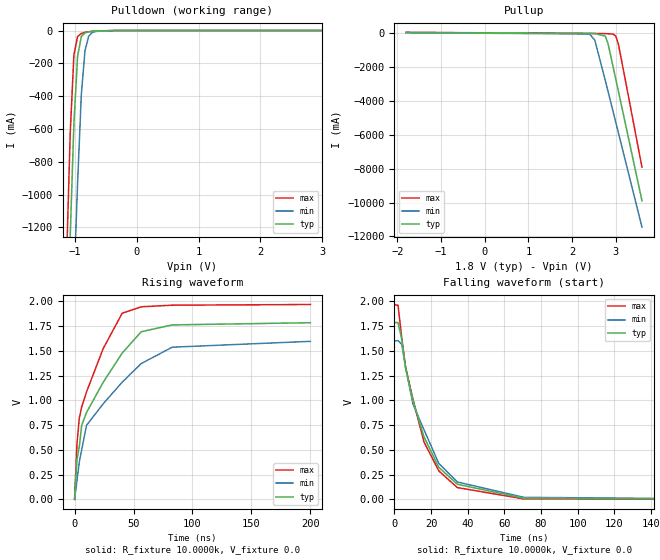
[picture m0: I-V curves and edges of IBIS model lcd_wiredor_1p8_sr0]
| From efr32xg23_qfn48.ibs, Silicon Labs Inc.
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|   Model lcd_wiredor_1p8_sr0
[Model]  lcd_wiredor_1p8_sr0
Model_type Output
Polarity   Non-Inverting
Enable   Active-Low
C_comp   1.6300pF   1.4000pF   2.7000pF
[Temperature Range]   25.0000   0.1250k   -40.0000
[Pullup Reference]   1.8000V   1.6200V   1.9800V
[Pulldown Reference]   0.0V   0.0V   0.0V
[POWER Clamp Reference]   1.8000V   1.6200V   1.9800V
[GND Clamp Reference]   0.0V   0.0V   0.0V
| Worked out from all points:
|   slope of the pullup table from 0 to 0.27 V, typ, clamps not added: 94.5 ohm
|   rising waveform, R_fixture 10.0000k, V_fixture 0.0: 20-80 % time 35.6ns typ, 44.7ns min, 24.8ns max; typ from 0 V to 1.78 V
|   falling waveform, R_fixture 10.0000k, V_fixture 0.0: 20-80 % time 17.6ns typ, 19.2ns min, 16.2ns max; typ from 1.78 V to 0 V
[Pulldown]
|Voltage   I(typ)   I(min)   I(max)
-1.8V     -9.867A    -9.569A    -10.32A
-1.14V    -1.973A    -2.773A    -1.419A
-1.08V    -1.26A     -2.157A    -630.4mA
-1.02V    -568mA     -1.543A    -149.7mA
-960mV    -155.8mA   -930mA     -35.74mA
-900mV    -37.3mA    -392mA     -18.17mA
-840mV    -13.92mA   -121.5mA   -10.46mA
-780mV    -8.725mA   -34.03mA   -7.422mA
-720mV    -4.294mA   -11.21mA   -4.92mA
-660mV    -2.711mA   -5.267mA   -2.939mA
-360mV    -18.79uA   -69.64uA   -6.715uA
3.6V      3.264nA    104.4nA    3.919nA
[Pullup]
|Voltage   I(typ)   I(min)   I(max)
-1.8V     44.26mA    33.72mA    55.37mA
2.4V      -9.562mA   -43.33mA   -10.84mA
2.52V     -13.93mA   -402.8mA   -11.94mA
2.76V     -169.7mA   -2.785A    -22.6mA
2.82V     -580.7mA   -3.402A    -26.69mA
2.94V     -1.986A    -4.637A    -50.48mA
3V        -2.702A    -5.256A    -164.4mA
3.06V     -3.418A    -5.874A    -642.8mA
3.12V     -4.136A    -6.493A    -1.431A
3.24V     -5.572A    -7.731A    -3.044A
3.3V      -6.291A    -8.35A     -3.852A
3.6V      -9.889A    -11.45A    -7.906A
[Ramp]
| variable   typ   min   max
dV/dt_r  1.0697/35.6318n   0.9571/44.7077n   1.1804/24.8364n
dV/dt_f  23.4738u/1.8662p   35.5334u/4.9249p   18.1164u/56.1366p
R_load = 10.0000k
[Rising Waveform]
R_fixture= 10.0000k
V_fixture= 0.0
V_fixture_min= 0.0
V_fixture_max= 0.0
|time   V(typ)   V(min)   V(max)
0s        3.312uV    55.57uV    2.87uV
2.02ns    400mV      185.7mV    558.5mV
4.04ns    537mV      380.3mV    823.1mV
6.061ns   747.9mV    500.8mV    933.8mV
10.1ns    875.7mV    745.9mV    1.083V
24.24ns   1.181V     964mV      1.521V
40.4ns    1.477V     1.183V     1.879V
56.57ns   1.692V     1.371V     1.944V
82.83ns   1.761V     1.536V     1.96V
200ns     1.783V     1.595V     1.967V
[Falling Waveform]
R_fixture= 10.0000k
V_fixture= 0.0
V_fixture_min= 0.0
V_fixture_max= 0.0
|time   V(typ)   V(min)   V(max)
0s        1.785V     1.6V       1.968V
2.02ns    1.786V     1.603V     1.959V
4.04ns    1.617V     1.565V     1.631V
6.061ns   1.329V     1.344V     1.343V
10.1ns    1.001V     964.5mV    1.013V
16.16ns   631.1mV    702.6mV    579.3mV
24.24ns   322.4mV    361.9mV    286.7mV
34.34ns   151.7mV    174.7mV    118.4mV
70.71ns   10.08mV    19.66mV    2.932mV
200ns     -102.5uV   787.1uV    -488.7uV
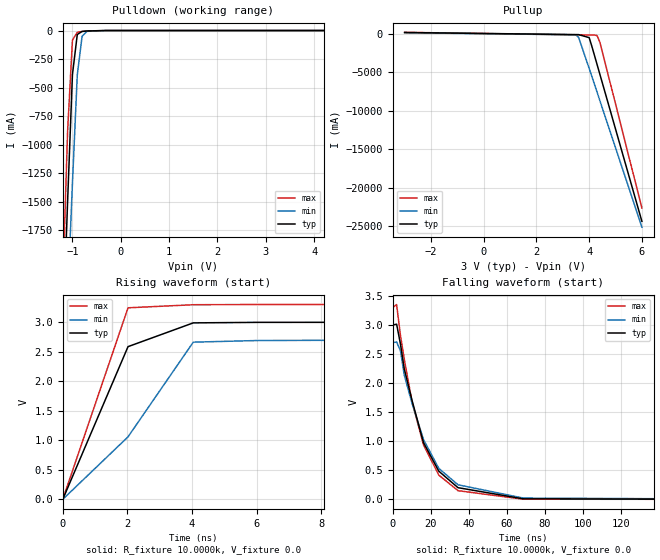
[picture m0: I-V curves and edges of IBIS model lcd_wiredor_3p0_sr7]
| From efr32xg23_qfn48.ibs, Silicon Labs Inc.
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|   Model lcd_wiredor_3p0_sr7
[Model]  lcd_wiredor_3p0_sr7
Model_type Output
Polarity   Non-Inverting
Enable   Active-Low
C_comp   1.6300pF   1.4000pF   2.7000pF
[Temperature Range]   25.0000   0.1250k   -40.0000
[Pullup Reference]   3.0000V   2.7000V   3.3000V
[Pulldown Reference]   0.0V   0.0V   0.0V
[POWER Clamp Reference]   3.0000V   2.7000V   3.3000V
[GND Clamp Reference]   0.0V   0.0V   0.0V
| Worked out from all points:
|   slope of the pullup table from 0 to 0.45 V, typ, clamps not added: 16.9 ohm
|   rising waveform, R_fixture 10.0000k, V_fixture 0.0: 20-80 % time 1.41ns typ, 2.38ns min, 1.23ns max; typ from 0 V to 3 V
|   falling waveform, R_fixture 10.0000k, V_fixture 0.0: 20-80 % time 16.5ns typ, 18.1ns min, 14.8ns max; typ from 3 V to 0 V
[Pulldown]
|Voltage   I(typ)   I(min)   I(max)
-3V       -24.27A    -21.95A    -26.57A
-1.2V     -2.686A    -3.389A    -2.22A
-1.1V     -1.495A    -2.361A    -881.8mA
-1V       -385.8mA   -1.337A    -84.19mA
-900mV    -34.99mA   -390.7mA   -14.95mA
-800mV    -7.703mA   -50.4mA    -8.403mA
-700mV    -3.742mA   -7.062mA   -4.219mA
-300mV    -2.847uA   -17.98uA   -692.6nA
6V        338.2nA    35.99uA    408.8nA
[Pullup]
|Voltage   I(typ)   I(min)   I(max)
-3V       194.2mA    164.1mA    218.3mA
3.5V      -78.04mA   -106.9mA   -111.5mA
3.6V      -80.27mA   -448.8mA   -111.7mA
4V        -471.9mA   -4.48A     -119.8mA
4.1V      -1.581A    -5.511A    -126.2mA
4.2V      -2.773A    -6.543A    -134.9mA
4.3V      -3.971A    -7.574A    -205.9mA
4.4V      -5.168A    -8.607A    -1.001A
4.5V      -6.366A    -9.639A    -2.34A
4.7V      -8.765A    -11.71A    -5.039A
4.8V      -9.964A    -12.74A    -6.39A
6V        -24.38A    -25.14A    -22.65A
[Ramp]
| variable   typ   min   max
dV/dt_r  1.7971/1.4057n   1.6163/2.3758n   1.9776/1.2331n
dV/dt_f  0.1139m/6.6269p   65.8711u/5.4048p   0.2002m/5.3470p
R_load = 10.0000k
[Rising Waveform]
R_fixture= 10.0000k
V_fixture= 0.0
V_fixture_min= 0.0
V_fixture_max= 0.0
|time   V(typ)   V(min)   V(max)
0s        4.624uV    47.91uV    4.748uV
2.02ns    2.583V     1.057V     3.24V
4.04ns    2.985V     2.659V     3.292V
6.061ns   2.994V     2.687V     3.296V
10.1ns    2.995V     2.693V     3.296V
200ns     2.995V     2.694V     3.296V
[Falling Waveform]
R_fixture= 10.0000k
V_fixture= 0.0
V_fixture_min= 0.0
V_fixture_max= 0.0
|time   V(typ)   V(min)   V(max)
0s        2.995V     2.694V     3.296V
2.02ns    3.01V      2.704V     3.348V
4.04ns    2.669V     2.555V     2.819V
6.061ns   2.239V     2.133V     2.405V
10.1ns    1.704V     1.654V     1.683V
16.16ns   975.4mV    1.028V     935.8mV
24.24ns   482.8mV    530.4mV    415.6mV
34.34ns   199.7mV    249.3mV    148.2mV
68.69ns   8.111mV    21.08mV    1.35mV
200ns     -452.2uV   289.4uV    -558.7uV
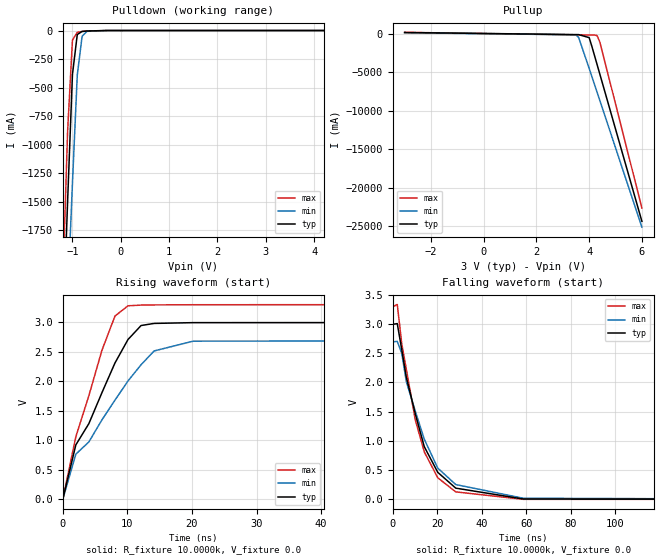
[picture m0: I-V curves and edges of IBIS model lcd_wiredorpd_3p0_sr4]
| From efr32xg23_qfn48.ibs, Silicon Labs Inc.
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|   Model lcd_wiredorpd_3p0_sr4
[Model]  lcd_wiredorpd_3p0_sr4
Model_type Output
Polarity   Non-Inverting
Enable   Active-Low
C_comp   1.6300pF   1.4000pF   2.7000pF
[Temperature Range]   25.0000   0.1250k   -40.0000
[Pullup Reference]   3.0000V   2.7000V   3.3000V
[Pulldown Reference]   0.0V   0.0V   0.0V
[POWER Clamp Reference]   3.0000V   2.7000V   3.3000V
[GND Clamp Reference]   0.0V   0.0V   0.0V
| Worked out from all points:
|   slope of the pulldown table from 0 to 0.45 V, typ, clamps not added: 40 kohm
|   slope of the pullup table from 0 to 0.45 V, typ, clamps not added: 16.9 ohm
|   rising waveform, R_fixture 10.0000k, V_fixture 0.0: 20-80 % time 7.22ns typ, 9.8ns min, 5.21ns max; typ from 0 V to 3 V
|   falling waveform, R_fixture 10.0000k, V_fixture 0.0: 20-80 % time 13.1ns typ, 14.6ns min, 11.6ns max; typ from 3 V to 0 V
[Pulldown]
|Voltage   I(typ)   I(min)   I(max)
-3V       -24.27A    -21.95A    -26.57A
-1.2V     -2.686A    -3.389A    -2.22A
-1.1V     -1.495A    -2.361A    -881.8mA
-1V       -385.8mA   -1.337A    -84.2mA
-900mV    -35.01mA   -390.8mA   -14.96mA
-800mV    -7.715mA   -50.41mA   -8.418mA
-700mV    -3.753mA   -7.071mA   -4.233mA
-300mV    -10.27uA   -24.2uA    -9.353uA
6V        150.3uA    165.9uA    174.4uA
[Pullup]
|Voltage   I(typ)   I(min)   I(max)
-3V       194.2mA    164.1mA    218.3mA
3.5V      -78.04mA   -106.9mA   -111.5mA
3.6V      -80.27mA   -448.8mA   -111.7mA
4V        -471.9mA   -4.48A     -119.8mA
4.1V      -1.581A    -5.511A    -126.2mA
4.2V      -2.773A    -6.543A    -134.9mA
4.3V      -3.971A    -7.574A    -205.9mA
4.4V      -5.168A    -8.607A    -1.001A
4.5V      -6.366A    -9.639A    -2.34A
4.7V      -8.765A    -11.71A    -5.039A
4.8V      -9.964A    -12.74A    -6.39A
6V        -24.38A    -25.14A    -22.65A
[Ramp]
| variable   typ   min   max
dV/dt_r  1.7971/7.2192n   1.6163/9.7974n   1.9776/5.2059n
dV/dt_f  0.3602/8.0619n   0.2884/10.2807n   0.4453/7.8494n
R_load = 10.0000k
[Rising Waveform]
R_fixture= 10.0000k
V_fixture= 0.0
V_fixture_min= 0.0
V_fixture_max= 0.0
|time   V(typ)   V(min)   V(max)
0s        3.563uV    38.12uV    3.534uV
2.02ns    921.1mV    764mV      1.059V
4.04ns    1.281V     970.8mV    1.754V
6.061ns   1.804V     1.344V     2.521V
8.081ns   2.307V     1.678V     3.101V
10.1ns    2.704V     2.003V     3.274V
12.12ns   2.94V      2.277V     3.286V
14.14ns   2.976V     2.51V      3.289V
20.2ns    2.989V     2.676V     3.292V
200ns     2.995V     2.694V     3.296V
[Falling Waveform]
R_fixture= 10.0000k
V_fixture= 0.0
V_fixture_min= 0.0
V_fixture_max= 0.0
|time   V(typ)   V(min)   V(max)
0s        2.995V     2.694V     3.296V
2.02ns    3.007V     2.703V     3.334V
4.04ns    2.559V     2.497V     2.661V
6.061ns   2.093V     2.016V     2.231V
10.1ns    1.465V     1.509V     1.36V
14.14ns   900.8mV    1.029V     812.1mV
20.2ns    461.4mV    533.7mV    368.2mV
28.28ns   190.7mV    252.1mV    126.5mV
58.59ns   5.202mV    17.91mV    -671.9uV
200ns     -336.2uV   209.1uV    -398uV
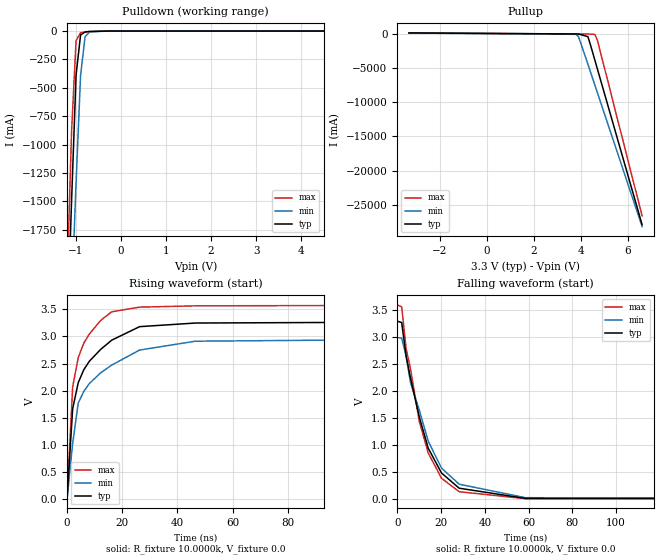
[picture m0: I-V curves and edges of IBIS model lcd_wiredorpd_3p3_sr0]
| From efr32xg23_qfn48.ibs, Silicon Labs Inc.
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|   Model lcd_wiredorpd_3p3_sr0
[Model]  lcd_wiredorpd_3p3_sr0
Model_type Output
Polarity   Non-Inverting
Enable   Active-Low
C_comp   1.6300pF   1.4000pF   2.7000pF
[Temperature Range]   25.0000   0.1250k   -40.0000
[Pullup Reference]   3.3000V   3.0000V   3.6000V
[Pulldown Reference]   0.0V   0.0V   0.0V
[POWER Clamp Reference]   3.3000V   3.0000V   3.6000V
[GND Clamp Reference]   0.0V   0.0V   0.0V
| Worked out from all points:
|   slope of the pulldown table from 0 to 0.495 V, typ, clamps not added: 39.9 kohm
|   slope of the pullup table from 0 to 0.495 V, typ, clamps not added: 57.6 ohm
|   rising waveform, R_fixture 10.0000k, V_fixture 0.0: 20-80 % time 8.71ns typ, 12.4ns min, 5.28ns max; typ from 0 V to 3.28 V
|   falling waveform, R_fixture 10.0000k, V_fixture 0.0: 20-80 % time 13.2ns typ, 14.6ns min, 11.7ns max; typ from 3.28 V to 0 V
[Pulldown]
|Voltage   I(typ)   I(min)   I(max)
-3.3V     -27.87A    -25.05A    -30.64A
-1.2V     -2.686A    -3.389A    -2.22A
-1.1V     -1.495A    -2.361A    -881.8mA
-1V       -385.8mA   -1.337A    -84.21mA
-900mV    -35.01mA   -390.8mA   -14.97mA
-800mV    -7.721mA   -50.41mA   -8.42mA
-700mV    -3.756mA   -7.077mA   -4.234mA
-300mV    -10.28uA   -24.24uA   -9.361uA
6.6V      165.9uA    283.9uA    192.3uA
[Pullup]
|Voltage   I(typ)   I(min)   I(max)
-3.3V     128.6mA    111mA      144.8mA
3.8V      -24.76mA   -73.78mA   -32.98mA
3.9V      -26.81mA   -415.6mA   -32.99mA
4.3V      -417.3mA   -4.446A    -40.25mA
4.4V      -1.526A    -5.477A    -46.31mA
4.5V      -2.718A    -6.509A    -54.56mA
4.6V      -3.914A    -7.541A    -125mA
4.7V      -5.113A    -8.573A    -919.5mA
4.8V      -6.311A    -9.606A    -2.259A
5V        -8.709A    -11.67A    -4.955A
5.1V      -9.909A    -12.7A     -6.309A
6.6V      -27.92A    -28.2A     -26.63A
[Ramp]
| variable   typ   min   max
dV/dt_r  1.9690/8.7077n   1.7856/12.4057n   2.1507/5.2799n
dV/dt_f  0.3967/8.5911n   0.3218/10.6703n   0.4859/8.3985n
R_load = 10.0000k
[Rising Waveform]
R_fixture= 10.0000k
V_fixture= 0.0
V_fixture_min= 0.0
V_fixture_max= 0.0
|time   V(typ)   V(min)   V(max)
0s        3.898uV    35.55uV    4.058uV
2.02ns    1.663V     1.02V      2.066V
4.04ns    2.145V     1.769V     2.607V
6.061ns   2.386V     1.985V     2.878V
8.081ns   2.543V     2.131V     3.046V
12.12ns   2.759V     2.326V     3.295V
16.16ns   2.932V     2.471V     3.457V
26.26ns   3.182V     2.749V     3.543V
46.46ns   3.249V     2.913V     3.567V
200ns     3.282V     2.976V     3.584V
[Falling Waveform]
R_fixture= 10.0000k
V_fixture= 0.0
V_fixture_min= 0.0
V_fixture_max= 0.0
|time   V(typ)   V(min)   V(max)
0s        3.283V     2.979V     3.586V
2.02ns    3.261V     2.973V     3.55V
4.04ns    2.643V     2.635V     2.781V
6.061ns   2.229V     2.144V     2.398V
10.1ns    1.506V     1.635V     1.424V
14.14ns   934.5mV    1.064V     846.2mV
20.2ns    475.3mV    566.4mV    379.2mV
28.28ns   193.3mV    267.4mV    128.5mV
58.59ns   4.5mV      17.78mV    -793.9uV
200ns     -361uV     115.4uV    -395.1uV
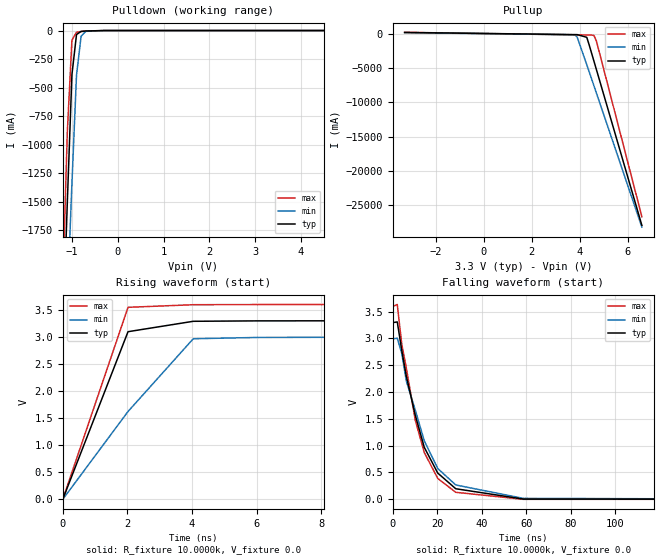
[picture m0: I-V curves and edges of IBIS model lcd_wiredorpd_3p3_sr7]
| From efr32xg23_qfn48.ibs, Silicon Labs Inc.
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|   Model lcd_wiredorpd_3p3_sr7
[Model]  lcd_wiredorpd_3p3_sr7
Model_type Output
Polarity   Non-Inverting
Enable   Active-Low
C_comp   1.6300pF   1.4000pF   2.7000pF
[Temperature Range]   25.0000   0.1250k   -40.0000
[Pullup Reference]   3.3000V   3.0000V   3.6000V
[Pulldown Reference]   0.0V   0.0V   0.0V
[POWER Clamp Reference]   3.3000V   3.0000V   3.6000V
[GND Clamp Reference]   0.0V   0.0V   0.0V
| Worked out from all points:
|   slope of the pulldown table from 0 to 0.495 V, typ, clamps not added: 39.9 kohm
|   slope of the pullup table from 0 to 0.495 V, typ, clamps not added: 15.9 ohm
|   rising waveform, R_fixture 10.0000k, V_fixture 0.0: 20-80 % time 1.29ns typ, 2.44ns min, 1.23ns max; typ from 0 V to 3.29 V
|   falling waveform, R_fixture 10.0000k, V_fixture 0.0: 20-80 % time 13ns typ, 14.5ns min, 11.5ns max; typ from 3.29 V to 0 V
[Pulldown]
|Voltage   I(typ)   I(min)   I(max)
-3.3V     -27.87A    -25.05A    -30.64A
-1.2V     -2.686A    -3.389A    -2.22A
-1.1V     -1.495A    -2.361A    -881.8mA
-1V       -385.8mA   -1.337A    -84.21mA
-900mV    -35.01mA   -390.8mA   -14.97mA
-800mV    -7.721mA   -50.41mA   -8.42mA
-700mV    -3.756mA   -7.077mA   -4.234mA
-300mV    -10.28uA   -24.24uA   -9.361uA
6.6V      165.9uA    283.9uA    192.3uA
[Pullup]
|Voltage   I(typ)   I(min)   I(max)
-3.3V     221.2mA    195.6mA    241.7mA
3.8V      -92.93mA   -118.6mA   -128.7mA
3.9V      -95.18mA   -460.7mA   -128.9mA
4.3V      -487mA     -4.492A    -137mA
4.4V      -1.596A    -5.524A    -143.5mA
4.5V      -2.788A    -6.555A    -152.2mA
4.6V      -3.984A    -7.588A    -223.2mA
4.7V      -5.183A    -8.62A     -1.018A
4.8V      -6.381A    -9.652A    -2.357A
5V        -8.78A     -11.72A    -5.054A
5.1V      -9.98A     -12.75A    -6.408A
6.6V      -28.01A    -28.26A    -26.74A
[Ramp]
| variable   typ   min   max
dV/dt_r  1.9770/1.2910n   1.7963/2.4384n   2.1574/1.2298n
dV/dt_f  0.3967/8.2579n   0.3218/10.1677n   0.4859/8.7175n
R_load = 10.0000k
[Rising Waveform]
R_fixture= 10.0000k
V_fixture= 0.0
V_fixture_min= 0.0
V_fixture_max= 0.0
|time   V(typ)   V(min)   V(max)
0s        3.898uV    35.55uV    4.058uV
2.02ns    3.094V     1.621V     3.544V
4.04ns    3.286V     2.964V     3.592V
6.061ns   3.294V     2.988V     3.595V
10.1ns    3.295V     2.993V     3.596V
200ns     3.295V     2.994V     3.596V
[Falling Waveform]
R_fixture= 10.0000k
V_fixture= 0.0
V_fixture_min= 0.0
V_fixture_max= 0.0
|time   V(typ)   V(min)   V(max)
0s        3.295V     2.994V     3.596V
2.02ns    3.308V     3.004V     3.633V
4.04ns    2.776V     2.719V     2.891V
6.061ns   2.3V       2.209V     2.453V
10.1ns    1.568V     1.664V     1.475V
14.14ns   968.7mV    1.091V     872.6mV
20.2ns    488.6mV    573.4mV    388.3mV
28.28ns   196.5mV    266.9mV    130.2mV
58.59ns   4.333mV    17.04mV    -877.3uV
200ns     -360.5uV   113.9uV    -395uV
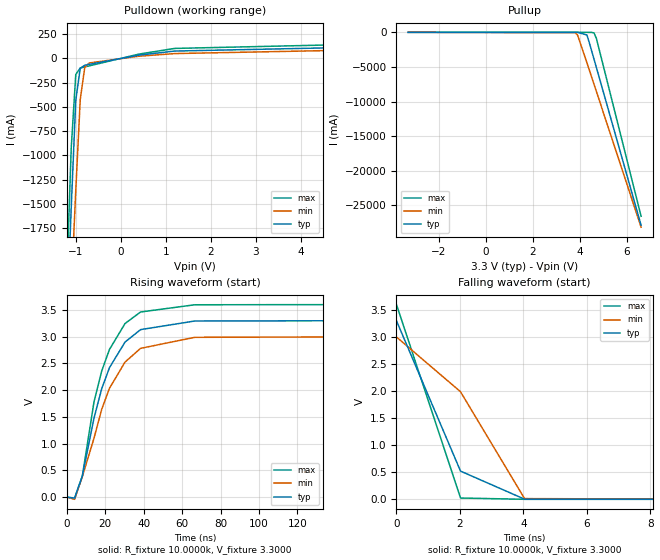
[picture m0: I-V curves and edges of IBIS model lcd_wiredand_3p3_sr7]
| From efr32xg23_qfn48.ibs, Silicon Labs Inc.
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|   Model lcd_wiredand_3p3_sr7
[Model]  lcd_wiredand_3p3_sr7
Model_type Output
Polarity   Inverting
Enable   Active-Low
C_comp   1.6300pF   1.4000pF   2.7000pF
[Temperature Range]   25.0000   0.1250k   -40.0000
[Pullup Reference]   3.3000V   3.0000V   3.6000V
[Pulldown Reference]   0.0V   0.0V   0.0V
[POWER Clamp Reference]   3.3000V   3.0000V   3.6000V
[GND Clamp Reference]   0.0V   0.0V   0.0V
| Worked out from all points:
|   slope of the pulldown table from 0 to 0.495 V, typ, clamps not added: 12.6 ohm
|   rising waveform, R_fixture 10.0000k, V_fixture 3.3000: 20-80 % time 15.5ns typ, 17.5ns min, 14.5ns max; typ from 0.004 V to 3.3 V
|   falling waveform, R_fixture 10.0000k, V_fixture 3.3000: 20-80 % time 1.44ns typ, 2.24ns min, 1.22ns max; typ from 3.3 V to 0.004 V
[Pulldown]
|Voltage   I(typ)   I(min)   I(max)
-3.3V     -27.9A     -25.09A    -30.67A
-1.2V     -2.717A    -3.413A    -2.255A
-1.1V     -1.526A    -2.386A    -916mA
-1V       -431.1mA   -1.361A    -166.1mA
-900mV    -101.3mA   -422.8mA   -99.6mA
-800mV    -71.14mA   -92.96mA   -88.1mA
-700mV    -61.69mA   -47.63mA   -77.54mA
400mV     32.64mA    21.8mA     43.42mA
1.2V      75.23mA    49.28mA    102.4mA
4.5V      107.1mA    79.43mA    136.7mA
5.5V      158.4mA    122.1mA    194.8mA
6.6V      244.5mA    192.8mA    297.9mA
[Pullup]
|Voltage   I(typ)   I(min)   I(max)
-3.3V     752.9nA    36.11uA    1.107uA
3.8V      -431uA     -50.4mA    -8.644nA
3.9V      -1.56mA    -390.8mA   -699.1nA
4.3V      -385.8mA   -4.417A    -4.22mA
4.4V      -1.495A    -5.446A    -8.405mA
4.5V      -2.686A    -6.476A    -14.95mA
4.6V      -3.88A     -7.507A    -84.19mA
4.7V      -5.077A    -8.538A    -881.8mA
4.8V      -6.274A    -9.569A    -2.22A
5V        -8.669A    -11.63A    -4.913A
5.1V      -9.868A    -12.66A    -6.266A
6.6V      -27.87A    -28.14A    -26.57A
[Ramp]
| variable   typ   min   max
dV/dt_r  -0.1735m/15.2480p   -0.1980m/40.4550p   -0.1322m/7.7387p
dV/dt_f  1.9778/1.4392n   1.7970/2.2414n   2.1582/1.2203n
R_load = 10.0000k
[Rising Waveform]
R_fixture= 10.0000k
V_fixture= 3.3000
V_fixture_min= 3.0000
V_fixture_max= 3.6000
|time   V(typ)   V(min)   V(max)
0s        3.595mV    4.859mV    2.976mV
4.04ns    -16.32mV   -39.68mV   -29.77mV
8.081ns   395.1mV    384mV      392.7mV
14.14ns   1.475V     1.099V     1.776V
18.18ns   2.028V     1.643V     2.359V
22.22ns   2.42V      2.036V     2.761V
30.3ns    2.898V     2.524V     3.244V
38.38ns   3.131V     2.781V     3.46V
66.67ns   3.292V     2.987V     3.595V
200ns     3.3V       3V         3.6V
[Falling Waveform]
R_fixture= 10.0000k
V_fixture= 3.3000
V_fixture_min= 3.0000
V_fixture_max= 3.6000
|time   V(typ)   V(min)   V(max)
0s        3.3V       3V         3.6V
2.02ns    523.7mV    1.989V     27.12mV
4.04ns    5.537mV    16.34mV    3.477mV
10.1ns    3.64mV     5.005mV    2.999mV
200ns     3.596mV    4.861mV    2.976mV
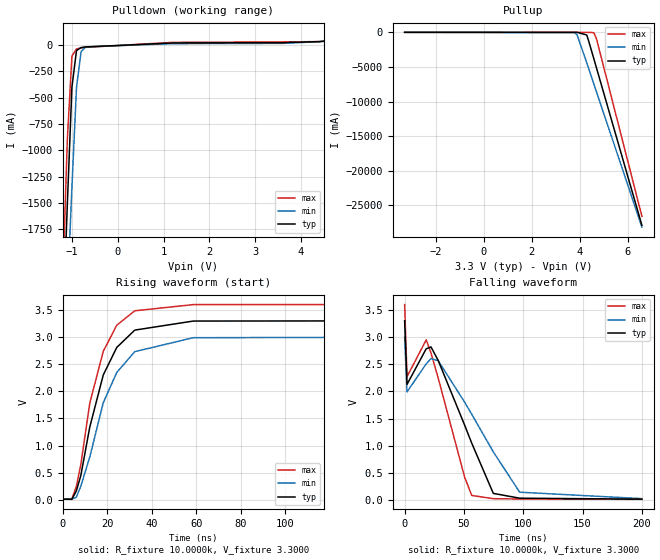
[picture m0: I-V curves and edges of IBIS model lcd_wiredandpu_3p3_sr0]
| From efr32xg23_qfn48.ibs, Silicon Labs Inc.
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|   Model lcd_wiredandpu_3p3_sr0
[Model]  lcd_wiredandpu_3p3_sr0
Model_type Output
Polarity   Inverting
Enable   Active-Low
C_comp   1.6300pF   1.4000pF   2.7000pF
[Temperature Range]   25.0000   0.1250k   -40.0000
[Pullup Reference]   3.3000V   3.0000V   3.6000V
[Pulldown Reference]   0.0V   0.0V   0.0V
[POWER Clamp Reference]   3.3000V   3.0000V   3.6000V
[GND Clamp Reference]   0.0V   0.0V   0.0V
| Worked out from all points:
|   slope of the pulldown table from 0 to 0.495 V, typ, clamps not added: 48.7 ohm
|   slope of the pullup table from 0 to 0.495 V, typ, clamps not added: 40.1 kohm
|   rising waveform, R_fixture 10.0000k, V_fixture 3.3000: 20-80 % time 12.7ns typ, 14.4ns min, 11.3ns max; typ from 0.013 V to 3.3 V
|   falling waveform, R_fixture 10.0000k, V_fixture 3.3000: 20-80 % time 36.1ns typ, 47.9ns min, 27.2ns max; typ from 3.3 V to 0.014 V
[Pulldown]
|Voltage   I(typ)   I(min)   I(max)
-3.3V     -27.9A     -25.09A    -30.67A
-1.2V     -2.696A    -3.401A    -2.23A
-1.1V     -1.505A    -2.373A    -891.3mA
-1V       -398.6mA   -1.347A    -105.6mA
-900mV    -52.92mA   -402.1mA   -36.92mA
-800mV    -24.42mA   -63.24mA   -28.77mA
-700mV    -18.71mA   -18.18mA   -22.69mA
1.2V      18.63mA    12.53mA    24.83mA
3.6V      21.79mA    15.2mA     28.99mA
4.4V      31.73mA    30.81mA    31.97mA
5.3V      66.78mA    62.14mA    67.97mA
6.6V      135.2mA    124.6mA    142.3mA
[Pullup]
|Voltage   I(typ)   I(min)   I(max)
-3.3V     82.22uA    106.9uA    95.53uA
3.8V      -523.4uA   -50.48mA   -109.5uA
3.9V      -1.654mA   -390.8mA   -113uA
4.3V      -385.9mA   -4.417A    -4.337mA
4.4V      -1.495A    -5.447A    -8.523mA
4.5V      -2.686A    -6.477A    -15.07mA
4.6V      -3.88A     -7.508A    -84.31mA
4.7V      -5.077A    -8.538A    -881.9mA
4.8V      -6.274A    -9.569A    -2.22A
5V        -8.669A    -11.63A    -4.914A
5.1V      -9.868A    -12.66A    -6.266A
6.6V      -27.87A    -28.14A    -26.57A
[Ramp]
| variable   typ   min   max
dV/dt_r  0.3946/12.8393n   0.3211/14.3172n   0.4830/11.5815n
dV/dt_f  1.9716/61.7876n   1.7855/80.1932n   2.1533/45.6223n
R_load = 10.0000k
[Rising Waveform]
R_fixture= 10.0000k
V_fixture= 3.3000
V_fixture_min= 3.0000
V_fixture_max= 3.6000
|time   V(typ)   V(min)   V(max)
0s        13.3mV     17.95mV    11.02mV
4.04ns    9.71mV     13.24mV    12.87mV
6.061ns   162.4mV    48.01mV    243.3mV
8.081ns   443.9mV    249.3mV    644.1mV
12.12ns   1.341V     790mV      1.782V
18.18ns   2.302V     1.789V     2.738V
24.24ns   2.809V     2.348V     3.219V
32.32ns   3.128V     2.731V     3.484V
58.59ns   3.295V     2.988V     3.598V
200ns     3.3V       3V         3.6V
[Falling Waveform]
R_fixture= 10.0000k
V_fixture= 3.3000
V_fixture_min= 3.0000
V_fixture_max= 3.6000
|time   V(typ)   V(min)   V(max)
0s        3.3V       3V         3.6V
2.02ns    2.129V     1.99V      2.271V
18.18ns   2.784V     2.507V     2.948V
22.22ns   2.818V     2.603V     2.708V
28.28ns   2.57V      2.565V     2.246V
50.51ns   1.381V     1.803V     425.3mV
56.57ns   1.045V     1.578V     82.47mV
74.75ns   120.5mV    884.6mV    23.25mV
96.97ns   32.26mV    142.5mV    17.28mV
200ns     13.93mV    24.1mV     11.08mV
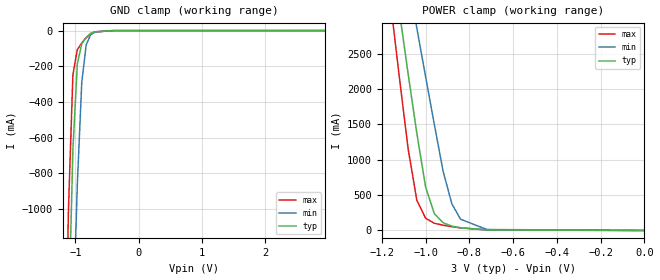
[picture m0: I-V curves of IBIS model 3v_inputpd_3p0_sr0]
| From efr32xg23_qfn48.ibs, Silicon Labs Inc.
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|   Model 3v_inputpd_3p0_sr0
[Model]  3v_inputpd_3p0_sr0
Model_type Input
C_comp   1.6300pF   1.4000pF   2.7000pF
[Temperature Range]   25.0000   0.1250k   -40.0000
[Pullup Reference]   3.0000V   2.7000V   3.3000V
[Pulldown Reference]   0.0V   0.0V   0.0V
[POWER Clamp Reference]   3.0000V   2.7000V   3.3000V
[GND Clamp Reference]   0.0V   0.0V   0.0V
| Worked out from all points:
|   GND clamp passes 1 mA (typ) near -0.51 V on its own axis
|   POWER clamp passes 1 mA (typ) near -0.53 V on its own axis
[GND_clamp]
|Voltage   I(typ)   I(min)   I(max)
-3V       -32.58A    -30.59A    -34.3A
-1.18V    -2.82A     -3.643A    -2.261A
-1.11V    -1.645A    -2.575A    -1.001A
-1.04V    -666.4mA   -1.673A    -246.5mA
-970mV    -186.7mA   -861.8mA   -106.7mA
-900mV    -73.87mA   -290.7mA   -68.99mA
-830mV    -38.02mA   -80.49mA   -39.64mA
-760mV    -15.98mA   -23.03mA   -17.38mA
-690mV    -6.623mA   -7.862mA   -7.305mA
-410mV    -126.1uA   -305.1uA   -67.37uA
2.95V     66.74uA    64.14uA    77.4uA
[POWER_clamp]
|Voltage   I(typ)   I(min)   I(max)
-3V       48.87A     43.6A      53.88A
-1.16V    4.026A     5.101A     3.218A
-1.12V    3.102A     4.315A     2.168A
-1.08V    2.218A     3.569A     1.158A
-1.04V    1.373A     2.862A     426mA
-1V       614.2mA    2.175A     173.2mA
-960mV    237.6mA    1.499A     101.6mA
-920mV    109.1mA    838.4mA    75.01mA
-880mV    61.34mA    377.2mA    54.12mA
-840mV    37.92mA    159.1mA    37.15mA
-720mV    7.491mA    13.65mA    7.97mA
0V        67.87uA    53.03uA    86.58uA
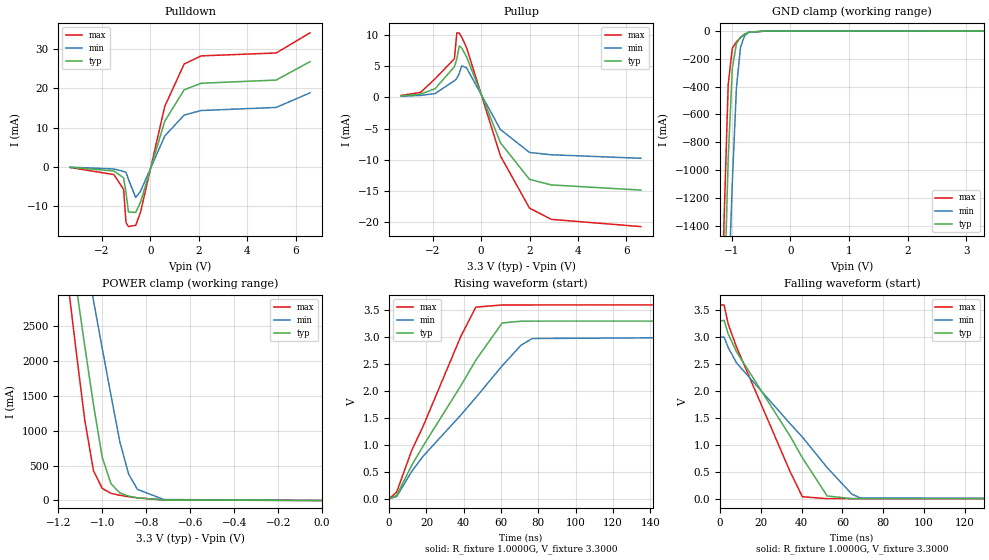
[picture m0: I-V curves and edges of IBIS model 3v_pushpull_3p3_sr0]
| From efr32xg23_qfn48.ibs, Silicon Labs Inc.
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|   Model 3v_pushpull_3p3_sr0
[Model]  3v_pushpull_3p3_sr0
Model_type 3-state
Polarity   Non-Inverting
Enable   Active-High
C_comp   1.6300pF   1.4000pF   2.7000pF
[Temperature Range]   25.0000   0.1250k   -40.0000
[Pullup Reference]   3.3000V   3.0000V   3.6000V
[Pulldown Reference]   0.0V   0.0V   0.0V
[POWER Clamp Reference]   3.3000V   3.0000V   3.6000V
[GND Clamp Reference]   0.0V   0.0V   0.0V
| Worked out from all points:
|   slope of the pulldown table from 0 to 0.495 V, typ, clamps not added: 49.5 ohm
|   slope of the pullup table from 0 to 0.495 V, typ, clamps not added: 103 ohm
|   GND clamp passes 1 mA (typ) near -0.52 V on its own axis
|   POWER clamp passes 1 mA (typ) near -0.53 V on its own axis
|   rising waveform, R_fixture 1.0000G, V_fixture 3.3000: 20-80 % time 34.9ns typ, 44.8ns min, 26.6ns max; typ from 0 V to 3.3 V
|   falling waveform, R_fixture 1.0000G, V_fixture 3.3000: 20-80 % time 32.4ns typ, 41.6ns min, 24.6ns max; typ from 3.3 V to 0 V
[Pulldown]
|Voltage   I(typ)   I(min)   I(max)
-3.3V     -190.3uA   -125.6uA   -223.1uA
-1.5V     -1.105mA   -602.5uA   -2.037mA
-1.1V     -2.851mA   -1.222mA   -5.805mA
-1V       -6.664mA   -1.499mA   -14.3mA
-900mV    -11.57mA   -3.242mA   -15.34mA
-600mV    -11.72mA   -7.896mA   -15.02mA
-400mV    -9.077mA   -6.282mA   -11.63mA
600mV     11.64mA    7.848mA    15.42mA
1.4V      19.66mA    13.19mA    26.26mA
2.1V      21.33mA    14.36mA    28.34mA
5.2V      22.15mA    15.15mA    29.08mA
6.6V      26.87mA    18.89mA    34.24mA
[Pullup]
|Voltage   I(typ)   I(min)   I(max)
-3.3V     240.6uA    173.6uA    305.4uA
-2.5V     504.9uA    306uA      783.5uA
-1.9V     1.376mA    598.3uA    2.961mA
-1.1V     4.904mA    2.673mA    6.193mA
-1V       6.161mA    3.043mA    10.34mA
-900mV    8.233mA    3.824mA    10.3mA
-800mV    7.911mA    5.047mA    9.658mA
-600mV    6.481mA    4.723mA    7.974mA
800mV     -7.292mA   -5.161mA   -9.398mA
2V        -13.15mA   -8.84mA    -17.76mA
2.9V      -14.04mA   -9.208mA   -19.56mA
6.6V      -14.87mA   -9.77mA    -20.72mA
[GND_clamp]
|Voltage   I(typ)   I(min)   I(max)
-3.3V     -36.82A    -34.37A    -38.92A
-1.2V     -3.169A    -3.961A    -2.635A
-1.13V    -1.976A    -2.875A    -1.354A
-1.06V    -919.5mA   -1.925A    -386.3mA
-990mV    -269.8mA   -1.092A    -124.2mA
-920mV    -91.07mA   -411.1mA   -78.21mA
-850mV    -46.3mA    -116.2mA   -47.38mA
-780mV    -21.47mA   -33.46mA   -23mA
-710mV    -8.335mA   -10.37mA   -9.191mA
-430mV    -188uA     -421.9uA   -101.6uA
3.3V      1.131nA    22.57uA    998.8pA
[POWER_clamp]
|Voltage   I(typ)   I(min)   I(max)
-3.28V    55.25A     49.02A     61.14A
-1.16V    4.026A     5.102A     3.218A
-1.12V    3.102A     4.316A     2.168A
-1.08V    2.218A     3.57A      1.158A
-1.04V    1.373A     2.863A     426mA
-1V       614.4mA    2.175A     173.2mA
-960mV    237.7mA    1.5A       101.5mA
-920mV    109.2mA    839mA      74.96mA
-880mV    61.4mA     377.7mA    54.07mA
-840mV    37.94mA    159.6mA    37.09mA
-720mV    7.455mA    13.75mA    7.89mA
0V        1.131nA    10.99nA    1.2nA
[Ramp]
| variable   typ   min   max
dV/dt_r  1.9607/37.2437n   1.7741/48.5853n   2.1439/28.0145n
dV/dt_f  1.9716/35.2845n   1.7876/46.7395n   2.1533/26.1360n
R_load = 10.0000k
[Rising Waveform]
R_fixture= 1.0000G
V_fixture= 3.3000
V_fixture_min= 3.0000
V_fixture_max= 3.6000
|time   V(typ)   V(min)   V(max)
0s        20.77uV    58.92uV    8.87uV
4.04ns    62.33mV    42.21mV    124.2mV
12.12ns   622.7mV    508.9mV    899.8mV
18.18ns   978.1mV    787.9mV    1.344V
38.38ns   2.095V     1.552V     3.012V
46.46ns   2.574V     1.879V     3.559V
60.61ns   3.265V     2.469V     3.599V
70.71ns   3.298V     2.852V     3.599V
76.77ns   3.299V     2.976V     3.599V
200ns     3.3V       3V         3.6V
[Falling Waveform]
R_fixture= 1.0000G
V_fixture= 3.3000
V_fixture_min= 3.0000
V_fixture_max= 3.6000
|time   V(typ)   V(min)   V(max)
0s        3.3V       3V         3.6V
2.02ns    3.314V     3.002V     3.598V
4.04ns    3.06V      2.807V     3.243V
8.081ns   2.731V     2.525V     2.818V
34.34ns   1.165V     1.395V     505.6mV
40.4ns    759.5mV    1.145V     36.12mV
52.53ns   50.6mV     577.2mV    644.6uV
64.65ns   1.158mV    85.01mV    347.3uV
68.69ns   845.5uV    14.63mV    303.4uV
200ns     21.06uV    60.43uV    9.025uV
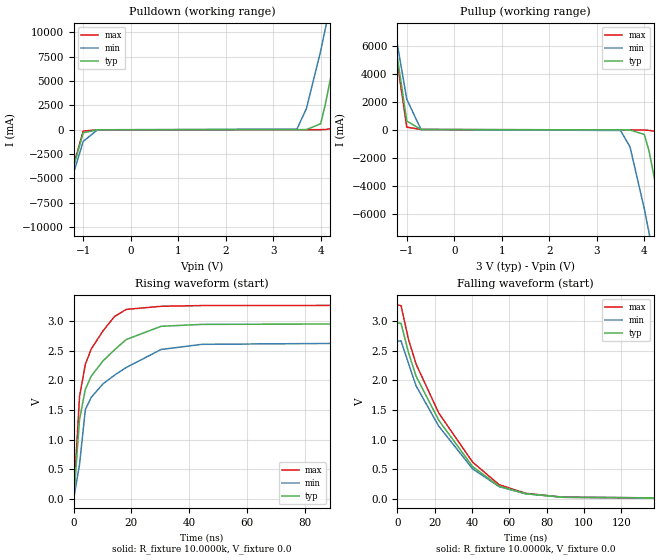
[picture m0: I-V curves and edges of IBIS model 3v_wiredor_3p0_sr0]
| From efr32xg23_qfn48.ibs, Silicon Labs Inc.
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|   Model 3v_wiredor_3p0_sr0
[Model]  3v_wiredor_3p0_sr0
Model_type Output
Polarity   Non-Inverting
Enable   Active-Low
C_comp   1.6300pF   1.4000pF   2.7000pF
[Temperature Range]   25.0000   0.1250k   -40.0000
[Pullup Reference]   3.0000V   2.7000V   3.3000V
[Pulldown Reference]   0.0V   0.0V   0.0V
[POWER Clamp Reference]   3.0000V   2.7000V   3.3000V
[GND Clamp Reference]   0.0V   0.0V   0.0V
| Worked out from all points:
|   slope of the pullup table from 0 to 0.45 V, typ, clamps not added: 109 ohm
|   rising waveform, R_fixture 10.0000k, V_fixture 0.0: 20-80 % time 10.2ns typ, 13.5ns min, 6.41ns max; typ from 0 V to 2.97 V
|   falling waveform, R_fixture 10.0000k, V_fixture 0.0: 20-80 % time 32.1ns typ, 31.9ns min, 32.9ns max; typ from 2.97 V to 0.001 V
[Pulldown]
|Voltage   I(typ)   I(min)   I(max)
-3V       -32.58A    -30.59A    -34.3A
-1.6V     -10.63A    -10.8A     -10.59A
-1V       -326.2mA   -1.208A    -136.7mA
-700mV    -7.458mA   -9.012mA   -8.238mA
3.5V      590.3uA    66.88mA    3.48nA
3.7V      6.154mA    2.175A     19.25uA
4V        614.1mA    8.096A     6.499mA
4.1V      2.659A     10.42A     23.04mA
4.3V      7.504A     15.17A     173.1mA
4.4V      10.17A     17.48A     1.662A
4.7V      18.27A     24.04A     10.12A
6V        48.87A     49.4A      46.09A
[Pullup]
|Voltage   I(typ)   I(min)   I(max)
-3V       48.87A     43.6A      53.88A
-1.3V     7.508A     8.098A     7.144A
-1V       620mA      2.177A     183.2mA
-700mV    13.08mA    14.83mA    15.17mA
3.5V      -12.66mA   -54.37mA   -17.26mA
3.7V      -19.43mA   -1.216A    -17.35mA
4V        -338.2mA   -5.618A    -25.61mA
4.1V      -1.494A    -7.337A    -46.11mA
4.3V      -4.985A    -10.81A    -154.1mA
4.4V      -6.859A    -12.49A    -854.6mA
4.8V      -14.26A    -18.6A     -8.603A
6V        -32.59A    -34.38A    -29.66A
[Ramp]
| variable   typ   min   max
dV/dt_r  1.7820/10.2391n   1.5965/13.5355n   1.9648/6.4124n
dV/dt_f  7.3780u/2.1659p   60.8091u/30.9987n   6.9199u/1.3463p
R_load = 10.0000k
[Rising Waveform]
R_fixture= 10.0000k
V_fixture= 0.0
V_fixture_min= 0.0
V_fixture_max= 0.0
|time   V(typ)   V(min)   V(max)
0s        10.14uV    88.71uV    13.83uV
2.02ns    1.34V      578.7mV    1.728V
4.04ns    1.85V      1.506V     2.272V
6.061ns   2.07V      1.712V     2.528V
10.1ns    2.326V     1.939V     2.833V
14.14ns   2.515V     2.088V     3.079V
18.18ns   2.69V      2.217V     3.199V
30.3ns    2.914V     2.522V     3.252V
44.44ns   2.946V     2.609V     3.264V
200ns     2.97V      2.661V     3.275V
[Falling Waveform]
R_fixture= 10.0000k
V_fixture= 0.0
V_fixture_min= 0.0
V_fixture_max= 0.0
|time   V(typ)   V(min)   V(max)
0s        2.971V     2.663V     3.275V
2.02ns    2.963V     2.667V     3.263V
6.061ns   2.465V     2.282V     2.686V
10.1ns    2.069V     1.906V     2.274V
22.22ns   1.327V     1.227V     1.448V
40.4ns    541.4mV    503.7mV    616.9mV
54.55ns   212.7mV    204.8mV    237.2mV
68.69ns   85.04mV    84.89mV    92.57mV
88.89ns   24.22mV    25.67mV    25.25mV
200ns     956.2uV    1.275mV    791.8uV
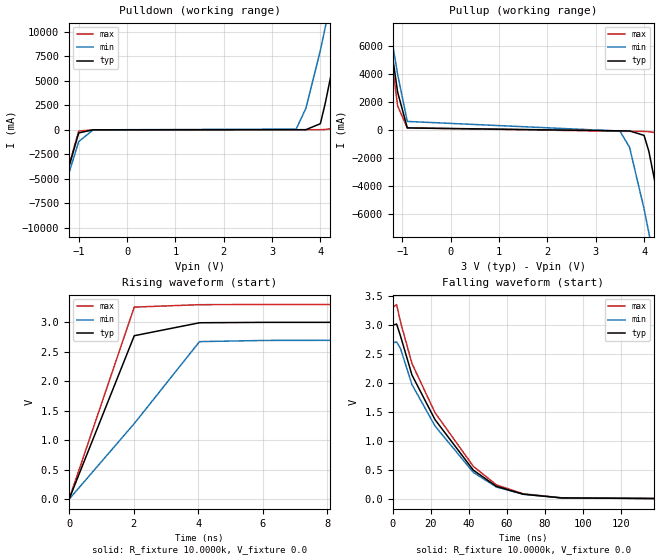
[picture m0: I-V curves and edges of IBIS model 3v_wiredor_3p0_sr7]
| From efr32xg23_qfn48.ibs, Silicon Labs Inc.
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|   Model 3v_wiredor_3p0_sr7
[Model]  3v_wiredor_3p0_sr7
Model_type Output
Polarity   Non-Inverting
Enable   Active-Low
C_comp   1.6300pF   1.4000pF   2.7000pF
[Temperature Range]   25.0000   0.1250k   -40.0000
[Pullup Reference]   3.0000V   2.7000V   3.3000V
[Pulldown Reference]   0.0V   0.0V   0.0V
[POWER Clamp Reference]   3.0000V   2.7000V   3.3000V
[GND Clamp Reference]   0.0V   0.0V   0.0V
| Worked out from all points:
|   slope of the pullup table from 0 to 0.45 V, typ, clamps not added: 16.9 ohm
|   rising waveform, R_fixture 10.0000k, V_fixture 0.0: 20-80 % time 1.31ns typ, 2.44ns min, 1.23ns max; typ from 0 V to 3 V
|   falling waveform, R_fixture 10.0000k, V_fixture 0.0: 20-80 % time 32.2ns typ, 31.9ns min, 32.9ns max; typ from 3 V to 0.001 V
[Pulldown]
|Voltage   I(typ)   I(min)   I(max)
-3V       -32.58A    -30.59A    -34.3A
-1.6V     -10.63A    -10.8A     -10.59A
-1V       -326.2mA   -1.208A    -136.7mA
-700mV    -7.458mA   -9.012mA   -8.238mA
3.5V      590.3uA    66.88mA    3.48nA
3.7V      6.154mA    2.175A     19.25uA
4V        614.1mA    8.096A     6.499mA
4.1V      2.659A     10.42A     23.04mA
4.3V      7.504A     15.17A     173.1mA
4.4V      10.17A     17.48A     1.662A
4.7V      18.27A     24.04A     10.12A
6V        48.87A     49.4A      46.09A
[Pullup]
|Voltage   I(typ)   I(min)   I(max)
-3V       48.87A     43.6A      53.88A
-1.3V     7.53A      8.107A     7.175A
-1.1V     2.691A     3.958A     1.702A
-900mV    131.1mA    593mA      129.1mA
3.5V      -77.88mA   -95.53mA   -111.5mA
3.7V      -84.81mA   -1.257A    -111.9mA
4V        -403.8mA   -5.659A    -120.5mA
4.1V      -1.56A     -7.378A    -141.1mA
4.3V      -5.051A    -10.85A    -249.3mA
4.4V      -6.924A    -12.54A    -949.9mA
4.8V      -14.32A    -18.64A    -8.699A
6V        -32.66A    -34.42A    -29.76A
[Ramp]
| variable   typ   min   max
dV/dt_r  1.7973/1.3115n   1.6165/2.4440n   1.9777/1.2285n
dV/dt_f  -7.2427u/0.6008p   49.0021u/19.3607n   -6.1952u/0.1482p
R_load = 10.0000k
[Rising Waveform]
R_fixture= 10.0000k
V_fixture= 0.0
V_fixture_min= 0.0
V_fixture_max= 0.0
|time   V(typ)   V(min)   V(max)
0s        10.14uV    88.71uV    13.83uV
2.02ns    2.768V     1.282V     3.252V
4.04ns    2.987V     2.668V     3.293V
6.061ns   2.994V     2.688V     3.296V
12.12ns   2.995V     2.694V     3.296V
200ns     2.995V     2.694V     3.296V
[Falling Waveform]
R_fixture= 10.0000k
V_fixture= 0.0
V_fixture_min= 0.0
V_fixture_max= 0.0
|time   V(typ)   V(min)   V(max)
0s        2.995V     2.694V     3.296V
2.02ns    3.014V     2.707V     3.35V
4.04ns    2.811V     2.595V     3.053V
10.1ns    2.138V     1.973V     2.335V
22.22ns   1.371V     1.262V     1.491V
42.42ns   501.3mV    463.2mV    566.6mV
54.55ns   224mV      212.6mV    249mV
68.69ns   89.04mV    87.3mV     96.79mV
88.89ns   25.13mV    26.07mV    26.24mV
200ns     961.6uV    1.28mV     796.3uV
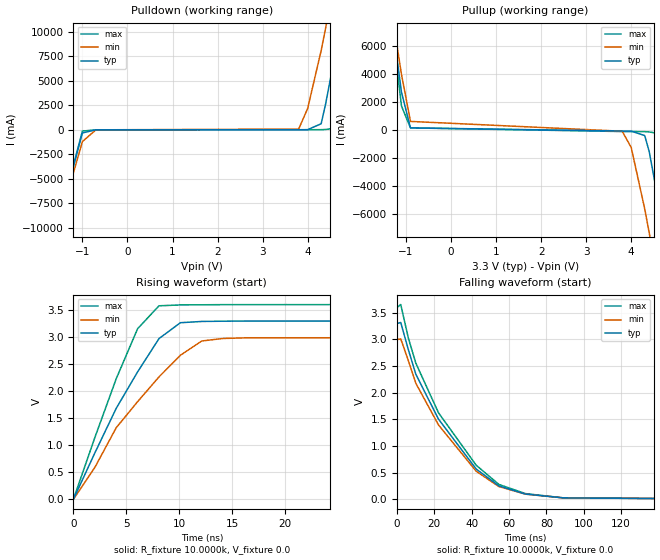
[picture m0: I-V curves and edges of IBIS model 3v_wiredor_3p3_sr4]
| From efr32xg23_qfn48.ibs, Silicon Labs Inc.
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|   Model 3v_wiredor_3p3_sr4
[Model]  3v_wiredor_3p3_sr4
Model_type Output
Polarity   Non-Inverting
Enable   Active-Low
C_comp   1.6300pF   1.4000pF   2.7000pF
[Temperature Range]   25.0000   0.1250k   -40.0000
[Pullup Reference]   3.3000V   3.0000V   3.6000V
[Pulldown Reference]   0.0V   0.0V   0.0V
[POWER Clamp Reference]   3.3000V   3.0000V   3.6000V
[GND Clamp Reference]   0.0V   0.0V   0.0V
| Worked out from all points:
|   slope of the pullup table from 0 to 0.495 V, typ, clamps not added: 15.9 ohm
|   rising waveform, R_fixture 10.0000k, V_fixture 0.0: 20-80 % time 5.44ns typ, 6.71ns min, 4.19ns max; typ from 0 V to 3.29 V
|   falling waveform, R_fixture 10.0000k, V_fixture 0.0: 20-80 % time 32.7ns typ, 32.4ns min, 33.5ns max; typ from 3.29 V to 0.001 V
[Pulldown]
|Voltage   I(typ)   I(min)   I(max)
-3.3V     -36.82A    -34.37A    -38.92A
-1.6V     -10.63A    -10.8A     -10.59A
-1V       -326.3mA   -1.208A    -136.6mA
-700mV    -7.474mA   -9.083mA   -8.231mA
3.8V      591.9uA    67.26mA    3.714nA
4V        6.191mA    2.175A     19.25uA
4.3V      614.4mA    8.098A     6.516mA
4.4V      2.66A      10.42A     23.07mA
4.6V      7.505A     15.17A     173.2mA
4.7V      10.17A     17.48A     1.662A
5V        18.27A     24.04A     10.12A
6.6V      55.71A     55.21A     53.88A
[Pullup]
|Voltage   I(typ)   I(min)   I(max)
-3.3V     55.71A     49.41A     61.67A
-1.3V     7.532A     8.11A      7.177A
-1.1V     2.692A     3.96A      1.703A
-900mV    133.8mA    595.4mA    130.8mA
3.8V      -92.75mA   -107.2mA   -128.7mA
4V        -99.72mA   -1.269A    -129.1mA
4.3V      -418.8mA   -5.671A    -137.7mA
4.4V      -1.575A    -7.39A     -158.3mA
4.6V      -5.066A    -10.86A    -266.6mA
4.7V      -6.939A    -12.55A    -967.1mA
5.1V      -14.34A    -18.65A    -8.716A
6.6V      -36.92A    -38.22A    -34.43A
[Ramp]
| variable   typ   min   max
dV/dt_r  1.9771/5.4354n   1.7964/6.7129n   2.1575/4.1880n
dV/dt_f  -6.5606u/0.4735p   51.0243u/19.5490n   -5.2783u/0.1116p
R_load = 10.0000k
[Rising Waveform]
R_fixture= 10.0000k
V_fixture= 0.0
V_fixture_min= 0.0
V_fixture_max= 0.0
|time   V(typ)   V(min)   V(max)
0s        13.25uV    93.35uV    24.31uV
2.02ns    854.4mV    587.8mV    1.138V
4.04ns    1.679V     1.321V     2.225V
6.061ns   2.352V     1.803V     3.149V
8.081ns   2.967V     2.26V      3.572V
10.1ns    3.26V      2.659V     3.588V
12.12ns   3.283V     2.923V     3.591V
14.14ns   3.288V     2.969V     3.593V
16.16ns   3.29V      2.98V      3.594V
200ns     3.295V     2.994V     3.596V
[Falling Waveform]
R_fixture= 10.0000k
V_fixture= 0.0
V_fixture_min= 0.0
V_fixture_max= 0.0
|time   V(typ)   V(min)   V(max)
0s        3.295V     2.994V     3.596V
2.02ns    3.316V     3.009V     3.653V
6.061ns   2.809V     2.605V     3.028V
10.1ns    2.346V     2.176V     2.552V
22.22ns   1.504V     1.395V     1.623V
42.42ns   567.4mV    525.9mV    638.7mV
54.55ns   252.7mV    240mV      280mV
68.69ns   99.91mV    97.88mV    108.4mV
88.89ns   27.9mV     28.82mV    29.16mV
200ns     964.2uV    1.279mV    806.4uV
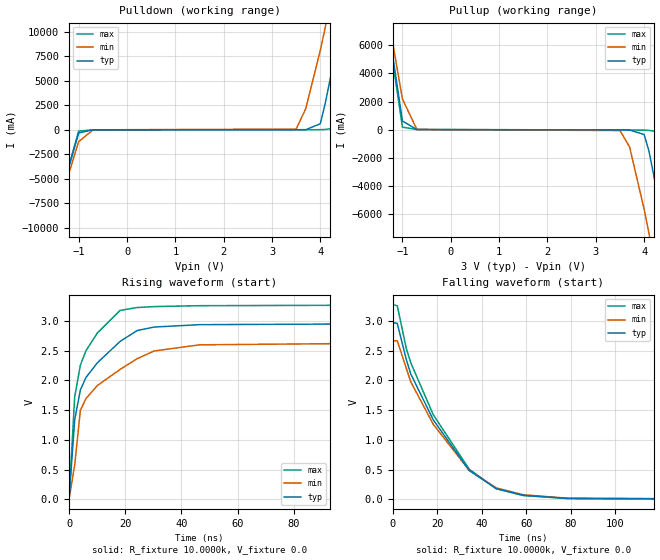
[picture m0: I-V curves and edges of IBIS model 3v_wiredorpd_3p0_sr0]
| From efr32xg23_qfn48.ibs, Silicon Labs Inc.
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|   Model 3v_wiredorpd_3p0_sr0
[Model]  3v_wiredorpd_3p0_sr0
Model_type Output
Polarity   Non-Inverting
Enable   Active-Low
C_comp   1.6300pF   1.4000pF   2.7000pF
[Temperature Range]   25.0000   0.1250k   -40.0000
[Pullup Reference]   3.0000V   2.7000V   3.3000V
[Pulldown Reference]   0.0V   0.0V   0.0V
[POWER Clamp Reference]   3.0000V   2.7000V   3.3000V
[GND Clamp Reference]   0.0V   0.0V   0.0V
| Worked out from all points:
|   slope of the pulldown table from 0 to 0.45 V, typ, clamps not added: 44.2 kohm
|   slope of the pullup table from 0 to 0.45 V, typ, clamps not added: 109 ohm
|   rising waveform, R_fixture 10.0000k, V_fixture 0.0: 20-80 % time 10.9ns typ, 14.5ns min, 6.79ns max; typ from 0 V to 2.97 V
|   falling waveform, R_fixture 10.0000k, V_fixture 0.0: 20-80 % time 26ns typ, 26.5ns min, 25.8ns max; typ from 2.97 V to 0.001 V
[Pulldown]
|Voltage   I(typ)   I(min)   I(max)
-3V       -32.58A    -30.59A    -34.3A
-1.6V     -10.63A    -10.8A     -10.59A
-1V       -326.2mA   -1.208A    -136.7mA
-700mV    -7.469mA   -9.021mA   -8.251mA
3.5V      668.1uA    66.94mA    91.83uA
3.7V      6.233mA    2.175A     116.2uA
4V        614.2mA    8.096A     6.599mA
4.1V      2.659A     10.42A     23.14mA
4.3V      7.504A     15.17A     173.2mA
4.4V      10.17A     17.48A     1.662A
4.7V      18.27A     24.04A     10.12A
6V        48.87A     49.4A      46.09A
[Pullup]
|Voltage   I(typ)   I(min)   I(max)
-3V       48.87A     43.6A      53.88A
-1.3V     7.508A     8.098A     7.144A
-1V       620mA      2.177A     183.2mA
-700mV    13.08mA    14.83mA    15.17mA
3.5V      -12.66mA   -54.38mA   -17.26mA
3.7V      -19.43mA   -1.216A    -17.35mA
4V        -338.2mA   -5.618A    -25.61mA
4.1V      -1.494A    -7.337A    -46.11mA
4.3V      -4.985A    -10.81A    -154.1mA
4.4V      -6.859A    -12.49A    -854.6mA
4.8V      -14.26A    -18.6A     -8.603A
6V        -32.59A    -34.38A    -29.66A
[Ramp]
| variable   typ   min   max
dV/dt_r  1.7820/10.9133n   1.5965/14.5224n   1.9648/6.7899n
dV/dt_f  0.3321/25.3031n   0.2660/26.7970n   0.4115/24.0523n
R_load = 10.0000k
[Rising Waveform]
R_fixture= 10.0000k
V_fixture= 0.0
V_fixture_min= 0.0
V_fixture_max= 0.0
|time   V(typ)   V(min)   V(max)
0s        8.184uV    73.48uV    10.86uV
2.02ns    1.337V     576.1mV    1.723V
4.04ns    1.839V     1.497V     2.256V
6.061ns   2.05V      1.697V     2.501V
10.1ns    2.296V     1.913V     2.797V
18.18ns   2.654V     2.184V     3.175V
24.24ns   2.837V     2.363V     3.224V
30.3ns    2.896V     2.494V     3.24V
46.46ns   2.936V     2.597V     3.255V
200ns     2.97V      2.661V     3.275V
[Falling Waveform]
R_fixture= 10.0000k
V_fixture= 0.0
V_fixture_min= 0.0
V_fixture_max= 0.0
|time   V(typ)   V(min)   V(max)
0s        2.971V     2.663V     3.275V
2.02ns    2.957V     2.666V     3.253V
6.061ns   2.354V     2.203V     2.538V
8.081ns   2.106V     1.974V     2.295V
18.18ns   1.336V     1.262V     1.422V
34.34ns   485.1mV    486.4mV    506.4mV
46.46ns   180.5mV    192.1mV    178.7mV
58.59ns   68.59mV    77.53mV    64.37mV
78.79ns   15.03mV    18.78mV    12.9mV
200ns     706.1uV    976.1uV    559.3uV
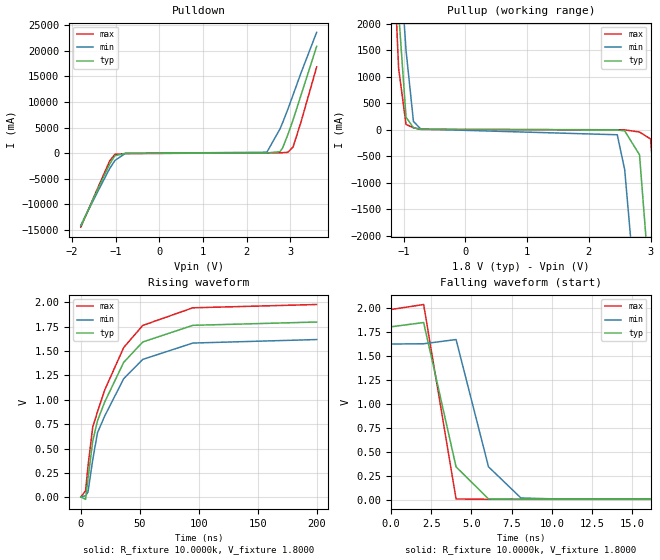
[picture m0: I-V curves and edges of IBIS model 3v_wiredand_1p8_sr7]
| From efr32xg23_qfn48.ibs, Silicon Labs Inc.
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|   Model 3v_wiredand_1p8_sr7
[Model]  3v_wiredand_1p8_sr7
Model_type Output
Polarity   Inverting
Enable   Active-Low
C_comp   1.6300pF   1.4000pF   2.7000pF
[Temperature Range]   25.0000   0.1250k   -40.0000
[Pullup Reference]   1.8000V   1.6200V   1.9800V
[Pulldown Reference]   0.0V   0.0V   0.0V
[POWER Clamp Reference]   1.8000V   1.6200V   1.9800V
[GND Clamp Reference]   0.0V   0.0V   0.0V
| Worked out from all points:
|   slope of the pulldown table from 0 to 0.27 V, typ, clamps not added: 19.5 ohm
|   rising waveform, R_fixture 10.0000k, V_fixture 1.8000: 20-80 % time 31.9ns typ, 32.1ns min, 32.1ns max; typ from 0.003 V to 1.8 V
|   falling waveform, R_fixture 10.0000k, V_fixture 1.8000: 20-80 % time 1.45ns typ, 1.54ns min, 1.18ns max; typ from 1.8 V to 0.003 V
[Pulldown]
|Voltage   I(typ)   I(min)   I(max)
-1.8V     -14.25A    -14.11A    -14.48A
-1.38V    -6.482A    -6.986A    -6.181A
-1.14V    -2.158A    -3.031A    -1.555A
-1.02V    -499.9mA   -1.449A    -234.9mA
-780mV    -64.11mA   -56.89mA   -83.8mA
2.46V     33.69mA    173.3mA    48.85mA
2.76V     265.6mA    4.718A     66.57mA
2.82V     988.4mA    5.927A     85.43mA
2.94V     3.59A      8.562A     149.7mA
3.06V     6.5A       11.38A     1.206A
3.24V     11.28A     15.64A     6.029A
3.6V      20.88A     23.62A     16.84A
[Pullup]
|Voltage   I(typ)   I(min)   I(max)
-1.8V     20.85A     19.71A     22.07A
-1.2V     4.976A     5.911A     4.296A
-1.08V    2.216A     3.565A     1.157A
-960mV    235.8mA    1.496A     100.8mA
-840mV    37.2mA     156.9mA    36.63mA
-720mV    7.125mA    12.82mA    7.666mA
2.46V     -4.689mA   -94.69mA   -342.9uA
2.58V     -21.13mA   -753.1mA   -2.576mA
2.82V     -472.4mA   -3.958A    -43.11mA
3V        -3.168A    -6.98A     -175.3mA
3.24V     -7.604A    -11.14A    -3.782A
3.6V      -14.24A    -16.86A    -10.99A
[Ramp]
| variable   typ   min   max
dV/dt_r  3.1329u/17.2462n   42.9256u/20.9663n   3.2780u/17.9611n
dV/dt_f  1.0782/1.4489n   0.9692/1.5408n   1.1867/1.1835n
R_load = 10.0000k
[Rising Waveform]
R_fixture= 10.0000k
V_fixture= 1.8000
V_fixture_min= 1.6200
V_fixture_max= 1.9800
|time   V(typ)   V(min)   V(max)
0s        2.94mV     4.53mV     2.085mV
4.04ns    -21.96mV   15mV       65.98mV
6.061ns   187.5mV    51.85mV    314.7mV
10.1ns    576.7mV    383.7mV    720.4mV
14.14ns   784.8mV    662.1mV    876.6mV
20.2ns    976mV      832.3mV    1.099V
36.36ns   1.385V     1.217V     1.537V
52.53ns   1.594V     1.415V     1.764V
94.95ns   1.765V     1.583V     1.945V
200ns     1.799V     1.619V     1.979V
[Falling Waveform]
R_fixture= 10.0000k
V_fixture= 1.8000
V_fixture_min= 1.6200
V_fixture_max= 1.9800
|time   V(typ)   V(min)   V(max)
0s        1.8V       1.62V      1.98V
2.02ns    1.844V     1.623V     2.032V
4.04ns    340.7mV    1.667V     5.954mV
6.061ns   6.186mV    341.2mV    2.365mV
8.081ns   3.463mV    16.17mV    2.138mV
10.1ns    3.083mV    6.808mV    2.107mV
16.16ns   2.965mV    4.688mV    2.094mV
200ns     2.941mV    4.533mV    2.085mV
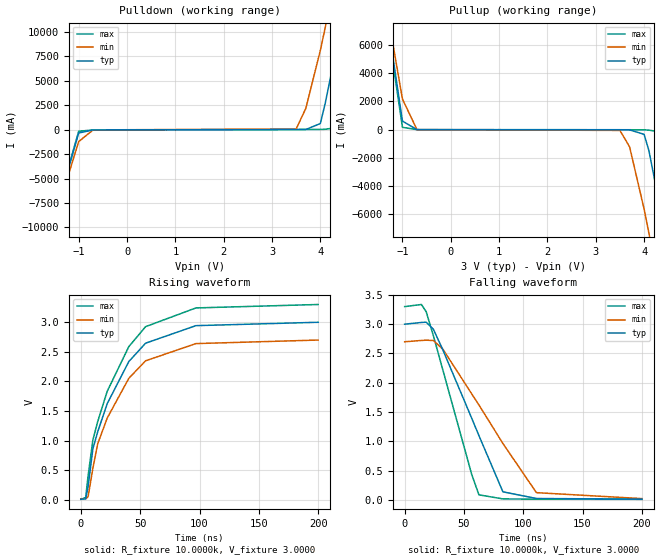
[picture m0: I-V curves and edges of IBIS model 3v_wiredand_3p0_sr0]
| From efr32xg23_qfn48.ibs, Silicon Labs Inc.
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|   Model 3v_wiredand_3p0_sr0
[Model]  3v_wiredand_3p0_sr0
Model_type Output
Polarity   Inverting
Enable   Active-Low
C_comp   1.6300pF   1.4000pF   2.7000pF
[Temperature Range]   25.0000   0.1250k   -40.0000
[Pullup Reference]   3.0000V   2.7000V   3.3000V
[Pulldown Reference]   0.0V   0.0V   0.0V
[POWER Clamp Reference]   3.0000V   2.7000V   3.3000V
[GND Clamp Reference]   0.0V   0.0V   0.0V
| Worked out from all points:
|   slope of the pulldown table from 0 to 0.45 V, typ, clamps not added: 51.6 ohm
|   rising waveform, R_fixture 10.0000k, V_fixture 3.0000: 20-80 % time 34.3ns typ, 34.4ns min, 34.6ns max; typ from 0.013 V to 3 V
|   falling waveform, R_fixture 10.0000k, V_fixture 3.0000: 20-80 % time 36.6ns typ, 48.9ns min, 26.9ns max; typ from 3 V to 0.014 V
[Pulldown]
|Voltage   I(typ)   I(min)   I(max)
-3V       -32.58A    -30.59A    -34.3A
-1.6V     -10.63A    -10.8A     -10.6A
-1V       -332.6mA   -1.21A     -150.8mA
-700mV    -19.14mA   -16.32mA   -23.31mA
3.5V      19.25mA    78.91mA    25.55mA
3.7V      24.82mA    2.187A     25.57mA
4V        632.8mA    8.108A     32.07mA
4.1V      2.678A     10.43A     48.62mA
4.3V      7.523A     15.18A     198.8mA
4.4V      10.19A     17.49A     1.688A
4.7V      18.29A     24.05A     10.15A
6V        48.89A     49.41A     46.12A
[Pullup]
|Voltage   I(typ)   I(min)   I(max)
-3V       48.87A     43.59A     53.88A
-1.3V     7.504A     8.096A     7.139A
-1V       614.1mA    2.175A     173.1mA
-700mV    6.154mA    10.05mA    6.499mA
3.5V      -715.9uA   -46.84mA   -9.332nA
3.7V      -7.458mA   -1.208A    -41.68uA
4V        -326.2mA   -5.611A    -8.238mA
4.1V      -1.482A    -7.329A    -28.72mA
4.3V      -4.973A    -10.8A     -136.7mA
4.4V      -6.846A    -12.49A    -837.1mA
4.8V      -14.25A    -18.59A    -8.585A
6V        -32.58A    -34.37A    -29.65A
[Ramp]
| variable   typ   min   max
dV/dt_r  5.8418u/19.2494n   52.3288u/21.1627n   8.1344u/19.5341n
dV/dt_f  1.7918/36.5919n   1.6062/48.8912n   1.9737/26.9075n
R_load = 10.0000k
[Rising Waveform]
R_fixture= 10.0000k
V_fixture= 3.0000
V_fixture_min= 2.7000
V_fixture_max= 3.3000
|time   V(typ)   V(min)   V(max)
0s        12.75mV    17.61mV    10.35mV
4.04ns    18.6mV     19.69mV    41.64mV
6.061ns   222.2mV    52.6mV     402.2mV
10.1ns    862.9mV    533mV      1.011V
14.14ns   1.148V     946.6mV    1.321V
22.22ns   1.627V     1.383V     1.835V
40.4ns    2.336V     2.053V     2.588V
54.55ns   2.646V     2.349V     2.925V
96.97ns   2.942V     2.639V     3.241V
200ns     2.999V     2.699V     3.299V
[Falling Waveform]
R_fixture= 10.0000k
V_fixture= 3.0000
V_fixture_min= 2.7000
V_fixture_max= 3.3000
|time   V(typ)   V(min)   V(max)
0s        3V         2.7V       3.3V
14.14ns   3.029V     2.722V     3.336V
18.18ns   3.034V     2.727V     3.212V
24.24ns   2.913V     2.721V     2.802V
32.32ns   2.557V     2.571V     2.211V
56.57ns   1.393V     1.81V      433.6mV
62.63ns   1.098V     1.621V     87.03mV
82.83ns   138.9mV    963.8mV    18.04mV
111.1ns   24.52mV    124.2mV    12.69mV
200ns     13.7mV     22.91mV    10.46mV
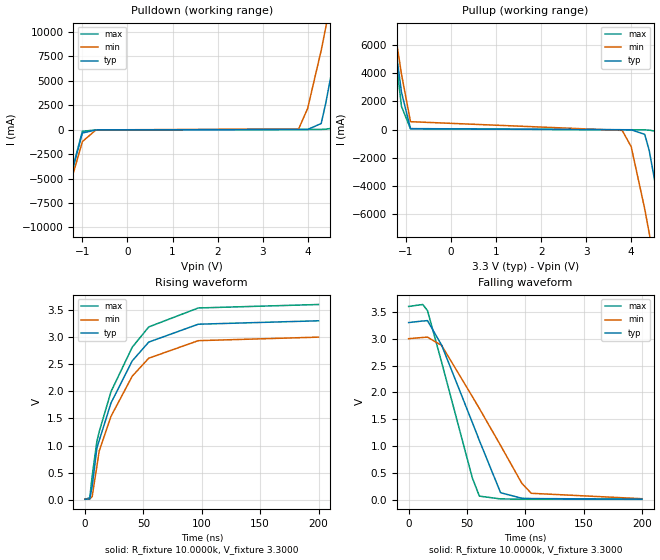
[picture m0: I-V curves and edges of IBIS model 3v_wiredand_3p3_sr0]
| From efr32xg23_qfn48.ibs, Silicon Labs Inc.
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|   Model 3v_wiredand_3p3_sr0
[Model]  3v_wiredand_3p3_sr0
Model_type Output
Polarity   Inverting
Enable   Active-Low
C_comp   1.6300pF   1.4000pF   2.7000pF
[Temperature Range]   25.0000   0.1250k   -40.0000
[Pullup Reference]   3.3000V   3.0000V   3.6000V
[Pulldown Reference]   0.0V   0.0V   0.0V
[POWER Clamp Reference]   3.3000V   3.0000V   3.6000V
[GND Clamp Reference]   0.0V   0.0V   0.0V
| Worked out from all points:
|   slope of the pulldown table from 0 to 0.495 V, typ, clamps not added: 49.5 ohm
|   rising waveform, R_fixture 10.0000k, V_fixture 3.3000: 20-80 % time 34.6ns typ, 34.7ns min, 34.9ns max; typ from 0.013 V to 3.3 V
|   falling waveform, R_fixture 10.0000k, V_fixture 3.3000: 20-80 % time 35.4ns typ, 47ns min, 26.2ns max; typ from 3.3 V to 0.014 V
[Pulldown]
|Voltage   I(typ)   I(min)   I(max)
-3.3V     -36.83A    -34.37A    -38.92A
-1.6V     -10.63A    -10.8A     -10.6A
-1V       -332.9mA   -1.21A     -150.9mA
-700mV    -19.59mA   -16.89mA   -23.52mA
3.8V      22.01mA    81.69mA    28.5mA
4V        27.62mA    2.19A      28.53mA
4.3V      635.9mA    8.112A     35.04mA
4.4V      2.681A     10.43A     51.61mA
4.6V      7.527A     15.18A     201.8mA
4.7V      10.19A     17.5A      1.691A
5V        18.29A     24.06A     10.15A
6.6V      55.74A     55.23A     53.91A
[Pullup]
|Voltage   I(typ)   I(min)   I(max)
-3.3V     55.71A     49.41A     61.66A
-1.3V     7.505A     8.098A     7.139A
-1.1V     2.66A      3.943A     1.662A
-900mV    80.57mA    570.7mA    64.27mA
3.8V      -716.7uA   -47.06mA   -10.86nA
4V        -7.474mA   -1.208A    -41.68uA
4.3V      -326.3mA   -5.611A    -8.231mA
4.4V      -1.482A    -7.33A     -28.7mA
4.6V      -4.973A    -10.8A     -136.6mA
4.7V      -6.847A    -12.49A    -837.1mA
5.1V      -14.25A    -18.59A    -8.585A
6.6V      -36.82A    -38.16A    -34.3A
[Ramp]
| variable   typ   min   max
dV/dt_r  7.7087u/19.5493n   55.1352u/21.1206n   14.4047u/19.8097n
dV/dt_f  1.9714/35.3895n   1.7862/46.9972n   2.1532/26.1957n
R_load = 10.0000k
[Rising Waveform]
R_fixture= 10.0000k
V_fixture= 3.3000
V_fixture_min= 3.0000
V_fixture_max= 3.6000
|time   V(typ)   V(min)   V(max)
0s        13.5mV     18.25mV    11.17mV
4.04ns    19.19mV    18.67mV    40.39mV
6.061ns   249.1mV    58.64mV    436.4mV
10.1ns    952.7mV    618.4mV    1.075V
12.12ns   1.095V     903.3mV    1.258V
22.22ns   1.786V     1.54V      1.994V
40.4ns    2.561V     2.279V     2.812V
54.55ns   2.907V     2.61V      3.186V
96.97ns   3.236V     2.933V     3.535V
200ns     3.299V     2.998V     3.599V
[Falling Waveform]
R_fixture= 10.0000k
V_fixture= 3.3000
V_fixture_min= 3.0000
V_fixture_max= 3.6000
|time   V(typ)   V(min)   V(max)
0s        3.3V       3V         3.6V
12.12ns   3.329V     3.023V     3.636V
16.16ns   3.336V     3.028V     3.522V
28.28ns   2.88V      2.875V     2.56V
54.55ns   1.442V     1.923V     410.6mV
60.61ns   1.105V     1.701V     71.1mV
78.79ns   134.1mV    1.013V     18.85mV
96.97ns   31.33mV    309.3mV    14.3mV
105.1ns   25.48mV    123.5mV    13.46mV
200ns     14.32mV    22.85mV    11.25mV
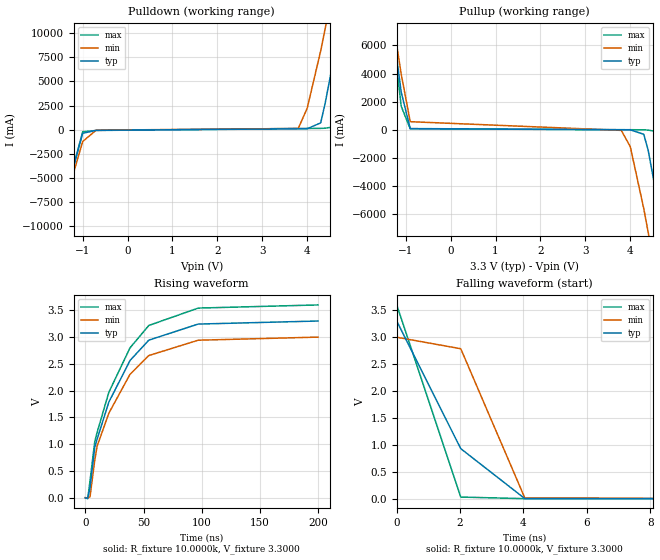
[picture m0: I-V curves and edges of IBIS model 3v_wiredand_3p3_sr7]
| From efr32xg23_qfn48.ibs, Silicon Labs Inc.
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|   Model 3v_wiredand_3p3_sr7
[Model]  3v_wiredand_3p3_sr7
Model_type Output
Polarity   Inverting
Enable   Active-Low
C_comp   1.6300pF   1.4000pF   2.7000pF
[Temperature Range]   25.0000   0.1250k   -40.0000
[Pullup Reference]   3.3000V   3.0000V   3.6000V
[Pulldown Reference]   0.0V   0.0V   0.0V
[POWER Clamp Reference]   3.3000V   3.0000V   3.6000V
[GND Clamp Reference]   0.0V   0.0V   0.0V
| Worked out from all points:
|   slope of the pulldown table from 0 to 0.495 V, typ, clamps not added: 12.7 ohm
|   rising waveform, R_fixture 10.0000k, V_fixture 3.3000: 20-80 % time 34.4ns typ, 34.3ns min, 34.9ns max; typ from 0.004 V to 3.3 V
|   falling waveform, R_fixture 10.0000k, V_fixture 3.3000: 20-80 % time 2.05ns typ, 1.31ns min, 1.22ns max; typ from 3.3 V to 0.004 V
[Pulldown]
|Voltage   I(typ)   I(min)   I(max)
-3.3V     -36.83A    -34.38A    -38.93A
-1.6V     -10.64A    -10.81A    -10.62A
-1V       -371.1mA   -1.224A    -213.8mA
-700mV    -62.65mA   -46.52mA   -78.49mA
3.8V      92.62mA    126.4mA    128.5mA
4V        98.53mA    2.235A     128.9mA
4.3V      707.5mA    8.157A     136.5mA
4.4V      2.753A     10.48A     153.5mA
4.6V      7.599A     15.23A     305.1mA
4.7V      10.27A     17.54A     1.795A
5V        18.37A     24.1A      10.26A
6.6V      55.85A     55.3A      54.07A
[Pullup]
|Voltage   I(typ)   I(min)   I(max)
-3.3V     55.71A     49.41A     61.66A
-1.3V     7.505A     8.098A     7.139A
-1.1V     2.66A      3.943A     1.662A
-900mV    80.57mA    570.7mA    64.27mA
3.8V      -716.7uA   -47.06mA   -10.86nA
4V        -7.474mA   -1.208A    -41.68uA
4.3V      -326.3mA   -5.611A    -8.231mA
4.4V      -1.482A    -7.33A     -28.7mA
4.6V      -4.973A    -10.8A     -136.6mA
4.7V      -6.847A    -12.49A    -837.1mA
5.1V      -14.25A    -18.59A    -8.585A
6.6V      -36.82A    -38.16A    -34.3A
[Ramp]
| variable   typ   min   max
dV/dt_r  7.7464u/19.3450n   55.4764u/20.8639n   14.4344u/19.6489n
dV/dt_f  1.9778/2.0451n   1.7970/1.3115n   2.1582/1.2224n
R_load = 10.0000k
[Rising Waveform]
R_fixture= 10.0000k
V_fixture= 3.3000
V_fixture_min= 3.0000
V_fixture_max= 3.6000
|time   V(typ)   V(min)   V(max)
0s        3.603mV    4.877mV    2.979mV
2.02ns    -11.41mV   -769.2uV   -14.01mV
4.04ns    192.9mV    22.41mV    322.2mV
8.081ns   944.9mV    700.9mV    1.049V
10.1ns    1.094V     963.6mV    1.22V
20.2ns    1.787V     1.58V      1.97V
38.38ns   2.562V     2.304V     2.798V
54.55ns   2.942V     2.655V     3.216V
96.97ns   3.242V     2.941V     3.54V
200ns     3.299V     2.999V     3.599V
[Falling Waveform]
R_fixture= 10.0000k
V_fixture= 3.3000
V_fixture_min= 3.0000
V_fixture_max= 3.6000
|time   V(typ)   V(min)   V(max)
0s        3.3V       3V         3.6V
2.02ns    932.3mV    2.787V     33.26mV
4.04ns    5.779mV    19.2mV     3.559mV
10.1ns    3.635mV    5.003mV    2.994mV
200ns     3.604mV    4.879mV    2.98mV
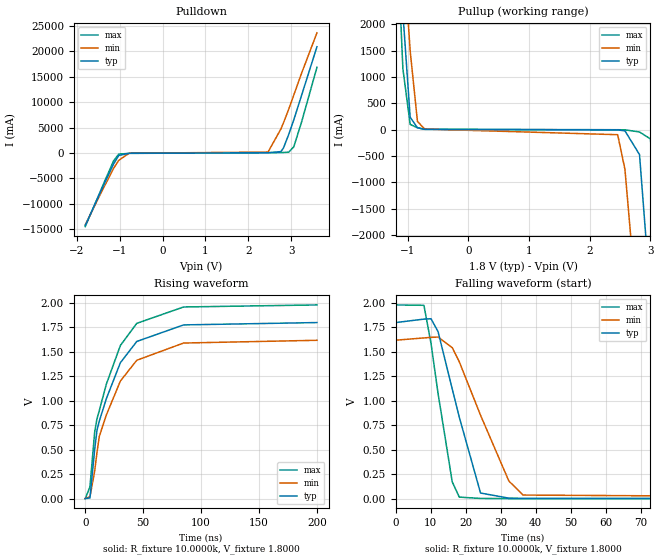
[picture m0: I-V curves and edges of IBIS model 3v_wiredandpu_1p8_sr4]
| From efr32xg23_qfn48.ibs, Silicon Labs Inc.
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|   Model 3v_wiredandpu_1p8_sr4
[Model]  3v_wiredandpu_1p8_sr4
Model_type Output
Polarity   Inverting
Enable   Active-Low
C_comp   1.6300pF   1.4000pF   2.7000pF
[Temperature Range]   25.0000   0.1250k   -40.0000
[Pullup Reference]   1.8000V   1.6200V   1.9800V
[Pulldown Reference]   0.0V   0.0V   0.0V
[POWER Clamp Reference]   1.8000V   1.6200V   1.9800V
[GND Clamp Reference]   0.0V   0.0V   0.0V
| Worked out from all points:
|   slope of the pulldown table from 0 to 0.27 V, typ, clamps not added: 19.5 ohm
|   slope of the pullup table from 0 to 0.27 V, typ, clamps not added: 45.3 kohm
|   rising waveform, R_fixture 10.0000k, V_fixture 1.8000: 20-80 % time 25.9ns typ, 26.8ns min, 25.3ns max; typ from 0.003 V to 1.8 V
|   falling waveform, R_fixture 10.0000k, V_fixture 1.8000: 20-80 % time 7.32ns typ, 11ns min, 5.05ns max; typ from 1.8 V to 0.003 V
[Pulldown]
|Voltage   I(typ)   I(min)   I(max)
-1.8V     -14.25A    -14.11A    -14.48A
-1.38V    -6.482A    -6.986A    -6.181A
-1.14V    -2.158A    -3.031A    -1.555A
-1.02V    -499.9mA   -1.449A    -234.9mA
-780mV    -64.11mA   -56.89mA   -83.8mA
2.46V     33.69mA    173.3mA    48.85mA
2.76V     265.6mA    4.718A     66.58mA
2.82V     988.4mA    5.927A     85.43mA
2.94V     3.59A      8.562A     149.7mA
3.06V     6.5A       11.38A     1.206A
3.24V     11.28A     15.64A     6.029A
3.6V      20.88A     23.62A     16.84A
[Pullup]
|Voltage   I(typ)   I(min)   I(max)
-1.8V     20.85A     19.71A     22.07A
-1.2V     4.976A     5.911A     4.296A
-1.08V    2.216A     3.565A     1.157A
-960mV    235.9mA    1.496A     100.8mA
-840mV    37.22mA    156.9mA    36.64mA
-720mV    7.136mA    12.83mA    7.68mA
2.46V     -4.739mA   -94.73mA   -404.8uA
2.58V     -21.18mA   -753.2mA   -2.639mA
2.82V     -472.4mA   -3.958A    -43.18mA
3V        -3.168A    -6.98A     -175.3mA
3.24V     -7.604A    -11.14A    -3.782A
3.6V      -14.24A    -16.86A    -10.99A
[Ramp]
| variable   typ   min   max
dV/dt_r  0.1949/16.6681n   0.1549/17.6415n   0.2429/15.8374n
dV/dt_f  1.0782/7.3234n   0.9692/11.0451n   1.1867/5.0456n
R_load = 10.0000k
[Rising Waveform]
R_fixture= 10.0000k
V_fixture= 1.8000
V_fixture_min= 1.6200
V_fixture_max= 1.9800
|time   V(typ)   V(min)   V(max)
0s        2.94mV     4.53mV     2.085mV
4.04ns    10.04mV    21.73mV    124.7mV
8.081ns   502.3mV    281mV      680.3mV
10.1ns    701.1mV    474.3mV    818.4mV
12.12ns   794.6mV    638.7mV    902.8mV
18.18ns   1.023V     856.3mV    1.171V
30.3ns    1.39V      1.203V     1.566V
44.44ns   1.607V     1.415V     1.792V
84.85ns   1.776V     1.591V     1.959V
200ns     1.8V       1.619V     1.98V
[Falling Waveform]
R_fixture= 10.0000k
V_fixture= 1.8000
V_fixture_min= 1.6200
V_fixture_max= 1.9800
|time   V(typ)   V(min)   V(max)
0s        1.8V       1.62V      1.98V
8.081ns   1.835V     1.643V     1.976V
10.1ns    1.839V     1.649V     1.588V
12.12ns   1.707V     1.652V     1.076V
16.16ns   1.122V     1.544V     173.5mV
18.18ns   833.6mV    1.399V     18.16mV
24.24ns   59.79mV    853.6mV    4.672mV
32.32ns   7.594mV    182.6mV    2.668mV
36.36ns   5.621mV    39.24mV    2.417mV
200ns     2.942mV    4.538mV    2.086mV
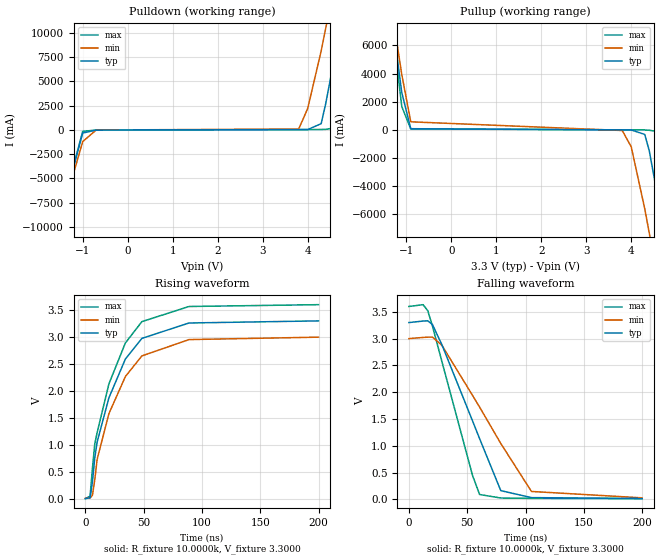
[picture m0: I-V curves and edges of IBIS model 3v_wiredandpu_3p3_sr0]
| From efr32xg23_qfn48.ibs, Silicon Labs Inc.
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|   Model 3v_wiredandpu_3p3_sr0
[Model]  3v_wiredandpu_3p3_sr0
Model_type Output
Polarity   Inverting
Enable   Active-Low
C_comp   1.6300pF   1.4000pF   2.7000pF
[Temperature Range]   25.0000   0.1250k   -40.0000
[Pullup Reference]   3.3000V   3.0000V   3.6000V
[Pulldown Reference]   0.0V   0.0V   0.0V
[POWER Clamp Reference]   3.3000V   3.0000V   3.6000V
[GND Clamp Reference]   0.0V   0.0V   0.0V
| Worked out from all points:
|   slope of the pulldown table from 0 to 0.495 V, typ, clamps not added: 49.5 ohm
|   slope of the pullup table from 0 to 0.495 V, typ, clamps not added: 44.2 kohm
|   rising waveform, R_fixture 10.0000k, V_fixture 3.3000: 20-80 % time 28ns typ, 28.7ns min, 27.3ns max; typ from 0.013 V to 3.3 V
|   falling waveform, R_fixture 10.0000k, V_fixture 3.3000: 20-80 % time 35.8ns typ, 47.6ns min, 26.5ns max; typ from 3.3 V to 0.014 V
[Pulldown]
|Voltage   I(typ)   I(min)   I(max)
-3.3V     -36.83A    -34.37A    -38.92A
-1.6V     -10.63A    -10.8A     -10.6A
-1V       -332.9mA   -1.21A     -150.9mA
-700mV    -19.59mA   -16.89mA   -23.52mA
3.8V      22.01mA    81.69mA    28.5mA
4V        27.62mA    2.19A      28.53mA
4.3V      635.9mA    8.112A     35.04mA
4.4V      2.681A     10.43A     51.61mA
4.6V      7.527A     15.18A     201.8mA
4.7V      10.19A     17.5A      1.691A
5V        18.29A     24.06A     10.15A
6.6V      55.74A     55.23A     53.91A
[Pullup]
|Voltage   I(typ)   I(min)   I(max)
-3.3V     55.71A     49.41A     61.66A
-1.3V     7.505A     8.098A     7.139A
-1.1V     2.66A      3.943A     1.662A
-900mV    80.58mA    570.7mA    64.28mA
3.8V      -800.8uA   -47.13mA   -99.31uA
4V        -7.56mA    -1.209A    -145.9uA
4.3V      -326.4mA   -5.611A    -8.338mA
4.4V      -1.482A    -7.33A     -28.81mA
4.6V      -4.973A    -10.8A     -136.7mA
4.7V      -6.847A    -12.49A    -837.2mA
5.1V      -14.25A    -18.59A    -8.585A
6.6V      -36.82A    -38.16A    -34.3A
[Ramp]
| variable   typ   min   max
dV/dt_r  0.3648/16.4028n   0.2963/17.5324n   0.4475/15.5974n
dV/dt_f  1.9713/35.8136n   1.7837/47.5632n   2.1532/26.5041n
R_load = 10.0000k
[Rising Waveform]
R_fixture= 10.0000k
V_fixture= 3.3000
V_fixture_min= 3.0000
V_fixture_max= 3.6000
|time   V(typ)   V(min)   V(max)
0s        13.5mV     18.25mV    11.17mV
4.04ns    26.64mV    25.25mV    57.08mV
6.061ns   319.6mV    73.39mV    569.4mV
8.081ns   766.3mV    360.9mV    1.027V
10.1ns    1.059V     738.5mV    1.233V
20.2ns    1.877V     1.585V     2.135V
34.34ns   2.595V     2.271V     2.892V
48.48ns   2.976V     2.652V     3.286V
88.89ns   3.261V     2.954V     3.566V
200ns     3.3V       2.999V     3.6V
[Falling Waveform]
R_fixture= 10.0000k
V_fixture= 3.3000
V_fixture_min= 3.0000
V_fixture_max= 3.6000
|time   V(typ)   V(min)   V(max)
0s        3.3V       3V         3.6V
12.12ns   3.328V     3.022V     3.634V
16.16ns   3.333V     3.027V     3.522V
20.2ns    3.262V     3.028V     3.234V
28.28ns   2.886V     2.876V     2.573V
54.55ns   1.465V     1.94V      446.7mV
60.61ns   1.133V     1.722V     89.52mV
78.79ns   161.7mV    1.042V     23.73mV
105.1ns   31.18mV    145.9mV    16.93mV
200ns     14.41mV    27.11mV    11.25mV
